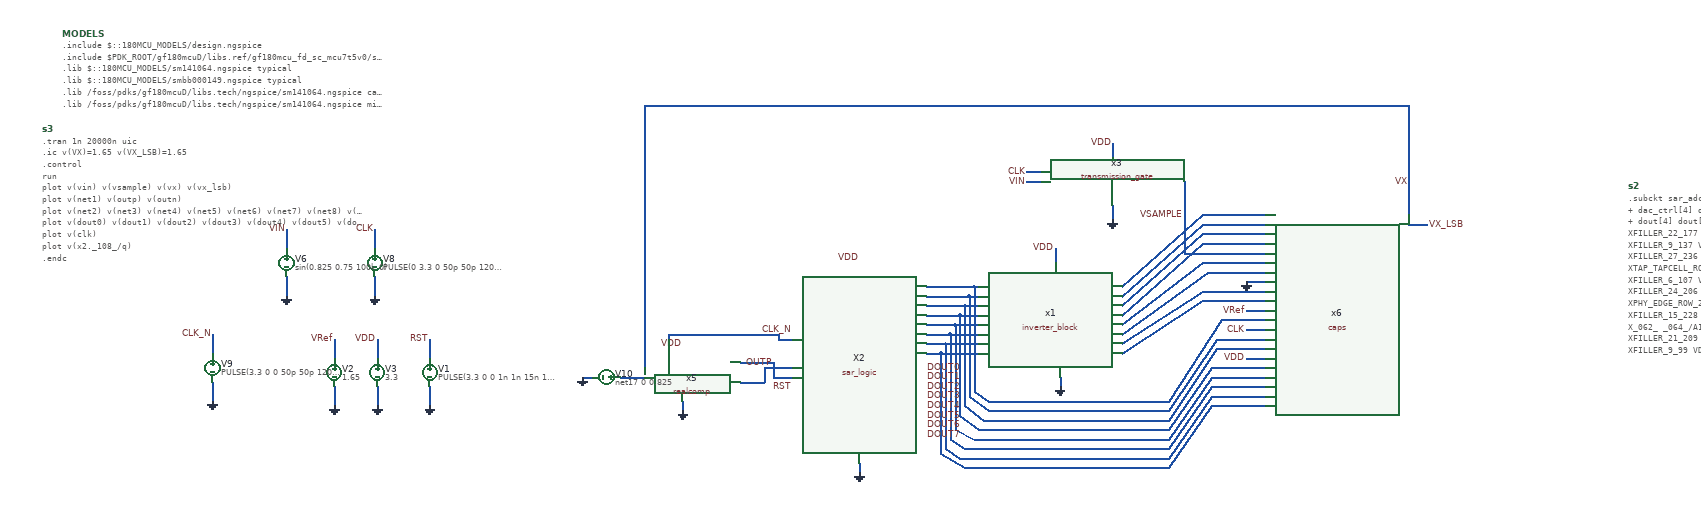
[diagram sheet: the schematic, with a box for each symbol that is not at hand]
v {xschem version=3.4.8RC file_version=1.3}
G {}
K {}
V {}
S {}
F {}
E {}
N 880 -1180 880 -1150 {lab=VDD}
N 1160 -890 1200 -890 {lab=0}
N 1160 -730 1200 -730 {lab=VDD}
N 700 -1120 730 -1120 {lab=CLK}
N 700 -1100 730 -1100 {lab=VIN}
N 1160 -830 1200 -830 {lab=VRef}
N 1160 -790 1200 -790 {lab=CLK}
N -20 -640 -20 -620 {lab=0}
N 100 -720 170 -720 {lab=OUTP}
N 880 -1050 880 -1020 {lab=0}
N 350 -510 350 -490 {lab=0}
N -50 -780 -50 -770 {lab=#net1}
N -50 -780 180 -780 {lab=#net1}
N 1030 -1100 1030 -950 {lab=VSAMPLE}
N 1030 -950 1200 -950 {lab=VSAMPLE}
N 590 -880 600 -880 {lab=#net2}
N 580 -860 600 -860 {lab=#net3}
N 570 -840 600 -840 {lab=#net4}
N 560 -820 600 -820 {lab=#net5}
N 550 -800 600 -800 {lab=#net6}
N 540 -780 600 -780 {lab=#net7}
N 530 -760 600 -760 {lab=#net8}
N 900 -880 1070 -1030 {lab=#net9}
N 1070 -1030 1200 -1030 {lab=#net9}
N 900 -860 1070 -1010 {lab=#net10}
N 1070 -1010 1200 -1010 {lab=#net10}
N 900 -840 1070 -990 {lab=#net11}
N 1070 -990 1200 -990 {lab=#net11}
N 900 -820 1070 -970 {lab=#net12}
N 1070 -970 1200 -970 {lab=#net12}
N 900 -800 1070 -930 {lab=#net13}
N 1070 -930 1200 -930 {lab=#net13}
N 900 -760 1070 -870 {lab=#net14}
N 1070 -870 1200 -870 {lab=#net14}
N 900 -740 1070 -850 {lab=#net15}
N 1070 -850 1200 -850 {lab=#net15}
N 620 -640 1000 -640 {lab=#net2}
N 620 -620 1000 -620 {lab=#net3}
N 1500 -1260 1500 -1030 {lab=VX}
N 1500 -1010 1540 -1010 {lab=VX_LSB}
N -665 -900 -665 -860 {lab=0}
N -665 -1000 -665 -960 {lab=CLK}
N -660 -670 -660 -630 {lab=0}
N -660 -770 -660 -730 {lab=VDD}
N -550 -670 -550 -630 {lab=0}
N -550 -770 -550 -730 {lab=RST}
N 760 -960 760 -930 {lab=VDD}
N 770 -690 770 -670 {lab=0}
N 590 -880 590 -660 {lab=#net2}
N 590 -660 620 -640 {lab=#net2}
N 580 -860 580 -650 {lab=#net3}
N 580 -650 620 -620 {lab=#net3}
N 570 -840 570 -630 {lab=#net4}
N 570 -630 610 -600 {lab=#net4}
N 610 -600 1000 -600 {lab=#net4}
N 560 -820 560 -610 {lab=#net5}
N 560 -610 600 -580 {lab=#net5}
N 600 -580 1000 -580 {lab=#net5}
N 550 -800 550 -580 {lab=#net6}
N 550 -580 590 -560 {lab=#net6}
N 590 -560 1000 -560 {lab=#net6}
N 540 -780 540 -560 {lab=#net7}
N 540 -560 570 -540 {lab=#net7}
N 570 -540 1000 -540 {lab=#net7}
N 490 -880 590 -880 {lab=#net2}
N 490 -860 580 -860 {lab=#net3}
N 490 -840 570 -840 {lab=#net4}
N 490 -820 560 -820 {lab=#net5}
N 490 -800 550 -800 {lab=#net6}
N 490 -780 540 -780 {lab=#net7}
N 490 -760 530 -760 {lab=#net8}
N 530 -760 530 -540 {lab=#net8}
N 530 -540 560 -520 {lab=#net8}
N 560 -520 1000 -520 {lab=#net8}
N 520 -740 600 -740 {lab=#net16}
N 520 -740 520 -530 {lab=#net16}
N 520 -530 570 -500 {lab=#net16}
N 570 -500 1000 -500 {lab=#net16}
N -100 -1260 -100 -710 {lab=VX}
N -100 -1260 1500 -1260 {lab=VX}
N -150 -690 -100 -690 {lab=#net17}
N -850 -1000 -850 -960 {lab=VIN}
N -850 -900 -850 -860 {lab=0}
N -750 -670 -750 -630 {lab=0}
N -750 -770 -750 -730 {lab=VRef}
N 1000 -640 1110 -810 {lab=#net2}
N 1110 -810 1200 -810 {lab=#net2}
N 1000 -620 1100 -770 {lab=#net3}
N 1100 -770 1200 -770 {lab=#net3}
N 1000 -600 1100 -750 {lab=#net4}
N 1100 -750 1200 -750 {lab=#net4}
N 1000 -580 1090 -710 {lab=#net5}
N 1090 -710 1200 -710 {lab=#net5}
N 1000 -560 1090 -690 {lab=#net6}
N 1090 -690 1200 -690 {lab=#net6}
N 1000 -540 1090 -670 {lab=#net7}
N 1090 -670 1200 -670 {lab=#net7}
N 1000 -520 1090 -650 {lab=#net8}
N 1090 -650 1200 -650 {lab=#net8}
N 1000 -500 1090 -630 {lab=#net16}
N 1090 -630 1200 -630 {lab=#net16}
N 900 -780 1080 -910 {lab=#net18}
N 1080 -910 1200 -910 {lab=#net18}
N 180 -780 180 -770 {lab=#net1}
N 180 -770 210 -770 {lab=#net1}
N 100 -680 150 -680 {lab=#net19}
N 150 -710 150 -680 {lab=#net19}
N 150 -710 210 -710 {lab=#net19}
N 170 -720 170 -690 {lab=OUTP}
N 170 -690 210 -690 {lab=OUTP}
N -1005 -680 -1005 -640 {lab=0}
N -1005 -780 -1005 -740 {lab=CLK_N}
N -230 -690 -210 -690 {lab=0}
N 490 -740 520 -740 {lab=#net16}
C {lab_wire.sym} 880 -1180 0 0 {name=p1 sig_type=std_logic lab=VDD}
C {lab_wire.sym} 1160 -730 0 0 {name=p2 sig_type=std_logic lab=VDD}
C {lab_wire.sym} 1160 -790 0 0 {name=p8 sig_type=std_logic lab=CLK}
C {lab_wire.sym} -20 -760 1 0 {name=p9 sig_type=std_logic lab=VDD}
C {code_shown.sym} 1960 -1090 0 0 {name=s2 only_toplevel=false 
value="
.subckt sar_adc_logic VDD VSS clk_i clk_o dac_ctrl[0] dac_ctrl[1] dac_ctrl[2] dac_ctrl[3]
+ dac_ctrl[4] dac_ctrl[5] dac_ctrl[6] dac_ctrl[7] dout[0] dout[1] dout[2] dout[3]
+ dout[4] dout[5] dout[6] dout[7] out_n out_p rst_n
XFILLER_22_177 VDD VDD VSS VSS gf180mcu_fd_sc_mcu7t5v0__fillcap_16
XFILLER_9_137 VDD VDD VSS VSS gf180mcu_fd_sc_mcu7t5v0__fill_2
XFILLER_27_236 VDD VDD VSS VSS gf180mcu_fd_sc_mcu7t5v0__fillcap_4
XTAP_TAPCELL_ROW_8_88 VDD VSS gf180mcu_fd_sc_mcu7t5v0__filltie
XFILLER_6_107 VDD VDD VSS VSS gf180mcu_fd_sc_mcu7t5v0__fill_1
XFILLER_24_206 VDD VDD VSS VSS gf180mcu_fd_sc_mcu7t5v0__fill_1
XPHY_EDGE_ROW_20_Left_50 VDD VDD VSS VSS gf180mcu_fd_sc_mcu7t5v0__endcap
XFILLER_15_228 VDD VDD VSS VSS gf180mcu_fd_sc_mcu7t5v0__fillcap_8
X_062_ _064_/A1 _105_/Q _106_/Q _063_/B VDD VDD VSS VSS gf180mcu_fd_sc_mcu7t5v0__aoi21_1
XFILLER_21_209 VDD VDD VSS VSS gf180mcu_fd_sc_mcu7t5v0__fill_1
XFILLER_9_99 VDD VDD VSS VSS gf180mcu_fd_sc_mcu7t5v0__fill_2
XFILLER_9_88 VDD VDD VSS VSS gf180mcu_fd_sc_mcu7t5v0__fill_1
XFILLER_9_66 VDD VDD VSS VSS gf180mcu_fd_sc_mcu7t5v0__fillcap_4
XFILLER_18_53 VDD VDD VSS VSS gf180mcu_fd_sc_mcu7t5v0__fillcap_8
X_045_ _087_/Q _057_/A1 VDD VDD VSS VSS gf180mcu_fd_sc_mcu7t5v0__clkinv_1
XFILLER_28_183 VDD VDD VSS VSS gf180mcu_fd_sc_mcu7t5v0__fillcap_32
Xhold30 _083_/Q _097_/D VDD VDD VSS VSS gf180mcu_fd_sc_mcu7t5v0__dlyc_1
XFILLER_4_227 VDD VDD VSS VSS gf180mcu_fd_sc_mcu7t5v0__fillcap_8
Xrebuffer28 _108_/Q wire22/I VDD VDD VSS VSS gf180mcu_fd_sc_mcu7t5v0__buf_8
XFILLER_6_34 VDD VDD VSS VSS gf180mcu_fd_sc_mcu7t5v0__fill_1
XFILLER_15_98 VDD VDD VSS VSS gf180mcu_fd_sc_mcu7t5v0__fill_1
XFILLER_25_120 VDD VDD VSS VSS gf180mcu_fd_sc_mcu7t5v0__fill_1
XFILLER_16_197 VDD VDD VSS VSS gf180mcu_fd_sc_mcu7t5v0__fill_2
Xoutput7 _086_/Q dac_ctrl[3] VDD VDD VSS VSS gf180mcu_fd_sc_mcu7t5v0__dlyd_1
XFILLER_22_101 VDD VDD VSS VSS gf180mcu_fd_sc_mcu7t5v0__fillcap_4
XFILLER_22_123 VDD VDD VSS VSS gf180mcu_fd_sc_mcu7t5v0__fill_2
XFILLER_10_159 VDD VDD VSS VSS gf180mcu_fd_sc_mcu7t5v0__fillcap_4
XTAP_TAPCELL_ROW_8_89 VDD VSS gf180mcu_fd_sc_mcu7t5v0__filltie
XFILLER_23_240 VDD VDD VSS VSS gf180mcu_fd_sc_mcu7t5v0__fill_1
XPHY_EDGE_ROW_21_Right_21 VDD VDD VSS VSS gf180mcu_fd_sc_mcu7t5v0__endcap
XPHY_EDGE_ROW_12_Right_12 VDD VDD VSS VSS gf180mcu_fd_sc_mcu7t5v0__endcap
XFILLER_0_36 VDD VDD VSS VSS gf180mcu_fd_sc_mcu7t5v0__fillcap_32
XFILLER_14_240 VDD VDD VSS VSS gf180mcu_fd_sc_mcu7t5v0__fill_1
XFILLER_2_177 VDD VDD VSS VSS gf180mcu_fd_sc_mcu7t5v0__fillcap_16
X_061_ _061_/A1 _104_/Q _061_/B _085_/D VDD VDD VSS VSS gf180mcu_fd_sc_mcu7t5v0__oai21_1
XFILLER_3_2 VDD VDD VSS VSS gf180mcu_fd_sc_mcu7t5v0__fillcap_64
XFILLER_18_65 VDD VDD VSS VSS gf180mcu_fd_sc_mcu7t5v0__fill_1
X_044_ _088_/Q _055_/A1 VDD VDD VSS VSS gf180mcu_fd_sc_mcu7t5v0__clkinv_1
XTAP_TAPCELL_ROW_5_79 VDD VSS gf180mcu_fd_sc_mcu7t5v0__filltie
Xclkbuf_1_1__f_valid_clk_regs clkbuf_0_valid_clk_regs/Z _104_/CLK VDD VDD VSS VSS
+ gf180mcu_fd_sc_mcu7t5v0__clkbuf_16
Xhold31 _089_/Q _091_/D VDD VDD VSS VSS gf180mcu_fd_sc_mcu7t5v0__dlyc_1
XFILLER_4_239 VDD VDD VSS VSS gf180mcu_fd_sc_mcu7t5v0__fill_2
XFILLER_28_173 VDD VDD VSS VSS gf180mcu_fd_sc_mcu7t5v0__fill_2
XFILLER_15_66 VDD VDD VSS VSS gf180mcu_fd_sc_mcu7t5v0__fillcap_4
XPHY_EDGE_ROW_6_Right_6 VDD VDD VSS VSS gf180mcu_fd_sc_mcu7t5v0__endcap
Xoutput10 _083_/Q dac_ctrl[6] VDD VDD VSS VSS gf180mcu_fd_sc_mcu7t5v0__dlyd_1
Xoutput8 _085_/Q dac_ctrl[4] VDD VDD VSS VSS gf180mcu_fd_sc_mcu7t5v0__dlyd_1
XFILLER_9_139 VDD VDD VSS VSS gf180mcu_fd_sc_mcu7t5v0__fill_1
Xdly_stage\\[31\\].delay_buf dly_stage\\[31\\].delay_buf/I comp_trigger_driver/I VDD VDD
+ VSS VSS gf180mcu_fd_sc_mcu7t5v0__buf_1
XFILLER_12_34 VDD VDD VSS VSS gf180mcu_fd_sc_mcu7t5v0__fill_1
XFILLER_18_227 VDD VDD VSS VSS gf180mcu_fd_sc_mcu7t5v0__fillcap_8
XFILLER_23_66 VDD VDD VSS VSS gf180mcu_fd_sc_mcu7t5v0__fillcap_4
XFILLER_2_123 VDD VDD VSS VSS gf180mcu_fd_sc_mcu7t5v0__fillcap_4
X_060_ _064_/A1 _104_/Q _105_/Q _061_/B VDD VDD VSS VSS gf180mcu_fd_sc_mcu7t5v0__aoi21_1
XFILLER_29_2 VDD VDD VSS VSS gf180mcu_fd_sc_mcu7t5v0__fillcap_32
X_043_ _089_/Q _053_/A1 VDD VDD VSS VSS gf180mcu_fd_sc_mcu7t5v0__clkinv_1
XPHY_EDGE_ROW_8_Left_38 VDD VDD VSS VSS gf180mcu_fd_sc_mcu7t5v0__endcap
XFILLER_7_237 VDD VDD VSS VSS gf180mcu_fd_sc_mcu7t5v0__fillcap_4
XFILLER_20_34 VDD VDD VSS VSS gf180mcu_fd_sc_mcu7t5v0__fill_1
Xhold32 _084_/Q _096_/D VDD VDD VSS VSS gf180mcu_fd_sc_mcu7t5v0__dlyc_1
XFILLER_6_69 VDD VDD VSS VSS gf180mcu_fd_sc_mcu7t5v0__fill_2
XFILLER_15_89 VDD VDD VSS VSS gf180mcu_fd_sc_mcu7t5v0__fill_1
XFILLER_16_111 VDD VDD VSS VSS gf180mcu_fd_sc_mcu7t5v0__fill_2
Xdly_stage\\[30\\].delay_buf dly_stage\\[30\\].delay_buf/I dly_stage\\[31\\].delay_buf/I
+ VDD VDD VSS VSS gf180mcu_fd_sc_mcu7t5v0__buf_1
Xoutput11 _090_/Q dac_ctrl[7] VDD VDD VSS VSS gf180mcu_fd_sc_mcu7t5v0__dlyd_1
Xoutput9 _084_/Q dac_ctrl[5] VDD VDD VSS VSS gf180mcu_fd_sc_mcu7t5v0__dlyd_1
XFILLER_16_177 VDD VDD VSS VSS gf180mcu_fd_sc_mcu7t5v0__fillcap_16
XFILLER_16_199 VDD VDD VSS VSS gf180mcu_fd_sc_mcu7t5v0__fill_1
XFILLER_13_136 VDD VDD VSS VSS gf180mcu_fd_sc_mcu7t5v0__fillcap_4
XTAP_TAPCELL_ROW_15_109 VDD VSS gf180mcu_fd_sc_mcu7t5v0__filltie
XFILLER_12_57 VDD VDD VSS VSS gf180mcu_fd_sc_mcu7t5v0__fill_2
XFILLER_27_228 VDD VDD VSS VSS gf180mcu_fd_sc_mcu7t5v0__fillcap_8
XFILLER_18_239 VDD VDD VSS VSS gf180mcu_fd_sc_mcu7t5v0__fill_2
XPHY_EDGE_ROW_24_Left_54 VDD VDD VSS VSS gf180mcu_fd_sc_mcu7t5v0__endcap
X_042_ _107_/Q _108_/D VDD VDD VSS VSS gf180mcu_fd_sc_mcu7t5v0__clkinv_1
Xhold33 _085_/Q _095_/D VDD VDD VSS VSS gf180mcu_fd_sc_mcu7t5v0__dlyc_1
XFILLER_6_37 VDD VDD VSS VSS gf180mcu_fd_sc_mcu7t5v0__fillcap_32
XFILLER_19_142 VDD VDD VSS VSS gf180mcu_fd_sc_mcu7t5v0__fill_1
XFILLER_25_167 VDD VDD VSS VSS gf180mcu_fd_sc_mcu7t5v0__fill_1
XFILLER_25_178 VDD VDD VSS VSS gf180mcu_fd_sc_mcu7t5v0__fill_1
Xoutput12 _091_/Q dout[0] VDD VDD VSS VSS gf180mcu_fd_sc_mcu7t5v0__dlyd_1
XPHY_EDGE_ROW_11_Left_41 VDD VDD VSS VSS gf180mcu_fd_sc_mcu7t5v0__endcap
XFILLER_16_101 VDD VDD VSS VSS gf180mcu_fd_sc_mcu7t5v0__fillcap_4
XTAP_TAPCELL_ROW_18_118 VDD VSS gf180mcu_fd_sc_mcu7t5v0__filltie
XFILLER_26_34 VDD VDD VSS VSS gf180mcu_fd_sc_mcu7t5v0__fill_1
XFILLER_7_80 VDD VDD VSS VSS gf180mcu_fd_sc_mcu7t5v0__fillcap_4
XFILLER_10_107 VDD VDD VSS VSS gf180mcu_fd_sc_mcu7t5v0__fill_2
XTAP_TAPCELL_ROW_20_124 VDD VSS gf180mcu_fd_sc_mcu7t5v0__filltie
XFILLER_5_133 VDD VDD VSS VSS gf180mcu_fd_sc_mcu7t5v0__fill_2
XFILLER_5_122 VDD VDD VSS VSS gf180mcu_fd_sc_mcu7t5v0__fill_2
XTAP_TAPCELL_ROW_0_60 VDD VSS gf180mcu_fd_sc_mcu7t5v0__filltie
XFILLER_18_24 VDD VDD VSS VSS gf180mcu_fd_sc_mcu7t5v0__fill_2
XTAP_TAPCELL_ROW_9_91 VDD VSS gf180mcu_fd_sc_mcu7t5v0__filltie
XFILLER_1_2 VDD VDD VSS VSS gf180mcu_fd_sc_mcu7t5v0__fillcap_32
Xclkload0 _107_/CLK clkload0/ZN VDD VDD VSS VSS gf180mcu_fd_sc_mcu7t5v0__inv_2
Xhold34 _088_/Q _092_/D VDD VDD VSS VSS gf180mcu_fd_sc_mcu7t5v0__dlyc_1
Xcomp_trigger_driver comp_trigger_driver/I output3/I VDD VDD VSS VSS gf180mcu_fd_sc_mcu7t5v0__buf_16
Xoutput13 _092_/Q dout[1] VDD VDD VSS VSS gf180mcu_fd_sc_mcu7t5v0__dlyd_1
XFILLER_24_190 VDD VDD VSS VSS gf180mcu_fd_sc_mcu7t5v0__fillcap_16
XTAP_TAPCELL_ROW_18_119 VDD VSS gf180mcu_fd_sc_mcu7t5v0__filltie
XPHY_EDGE_ROW_28_Right_28 VDD VDD VSS VSS gf180mcu_fd_sc_mcu7t5v0__endcap
XPHY_EDGE_ROW_19_Right_19 VDD VDD VSS VSS gf180mcu_fd_sc_mcu7t5v0__endcap
XTAP_TAPCELL_ROW_23_133 VDD VSS gf180mcu_fd_sc_mcu7t5v0__filltie
XFILLER_12_37 VDD VDD VSS VSS gf180mcu_fd_sc_mcu7t5v0__fillcap_16
XTAP_TAPCELL_ROW_20_125 VDD VSS gf180mcu_fd_sc_mcu7t5v0__filltie
Xclkbuf_0_valid_clk valid_clk_xor/Z clkbuf_0_valid_clk/Z VDD VDD VSS VSS gf180mcu_fd_sc_mcu7t5v0__clkbuf_16
XTAP_TAPCELL_ROW_9_92 VDD VSS gf180mcu_fd_sc_mcu7t5v0__filltie
XTAP_TAPCELL_ROW_0_61 VDD VSS gf180mcu_fd_sc_mcu7t5v0__filltie
XFILLER_27_2 VDD VDD VSS VSS gf180mcu_fd_sc_mcu7t5v0__fillcap_64
XFILLER_20_37 VDD VDD VSS VSS gf180mcu_fd_sc_mcu7t5v0__fillcap_64
Xhold35 _087_/Q _093_/D VDD VDD VSS VSS gf180mcu_fd_sc_mcu7t5v0__dlyc_1
XTAP_TAPCELL_ROW_6_82 VDD VSS gf180mcu_fd_sc_mcu7t5v0__filltie
Xclkbuf_1_0__f_eoc clkbuf_0_eoc/Z comp_trigger_nor/A2 VDD VDD VSS VSS gf180mcu_fd_sc_mcu7t5v0__clkbuf_16
Xoutput14 _093_/Q dout[2] VDD VDD VSS VSS gf180mcu_fd_sc_mcu7t5v0__dlyd_1
XTAP_TAPCELL_ROW_26_142 VDD VSS gf180mcu_fd_sc_mcu7t5v0__filltie
XFILLER_7_93 VDD VDD VSS VSS gf180mcu_fd_sc_mcu7t5v0__fill_1
XTAP_TAPCELL_ROW_23_134 VDD VSS gf180mcu_fd_sc_mcu7t5v0__filltie
XFILLER_27_209 VDD VDD VSS VSS gf180mcu_fd_sc_mcu7t5v0__fill_1
XTAP_TAPCELL_ROW_20_126 VDD VSS gf180mcu_fd_sc_mcu7t5v0__filltie
XFILLER_5_135 VDD VDD VSS VSS gf180mcu_fd_sc_mcu7t5v0__fill_1
XFILLER_5_124 VDD VDD VSS VSS gf180mcu_fd_sc_mcu7t5v0__fill_1
XFILLER_23_212 VDD VDD VSS VSS gf180mcu_fd_sc_mcu7t5v0__fillcap_16
XFILLER_4_61 VDD VDD VSS VSS gf180mcu_fd_sc_mcu7t5v0__fill_1
XFILLER_2_127 VDD VDD VSS VSS gf180mcu_fd_sc_mcu7t5v0__fill_2
XTAP_TAPCELL_ROW_9_93 VDD VSS gf180mcu_fd_sc_mcu7t5v0__filltie
XTAP_TAPCELL_ROW_0_62 VDD VSS gf180mcu_fd_sc_mcu7t5v0__filltie
XFILLER_18_26 VDD VDD VSS VSS gf180mcu_fd_sc_mcu7t5v0__fill_1
XFILLER_18_37 VDD VDD VSS VSS gf180mcu_fd_sc_mcu7t5v0__fillcap_16
X_099_ _100_/Q _099_/RN _104_/CLK _099_/Q VDD VDD VSS VSS gf180mcu_fd_sc_mcu7t5v0__dffrnq_1
XPHY_EDGE_ROW_28_Left_58 VDD VDD VSS VSS gf180mcu_fd_sc_mcu7t5v0__endcap
XFILLER_28_101 VDD VDD VSS VSS gf180mcu_fd_sc_mcu7t5v0__fillcap_4
XFILLER_29_36 VDD VDD VSS VSS gf180mcu_fd_sc_mcu7t5v0__fillcap_32
Xhold36 _086_/Q _094_/D VDD VDD VSS VSS gf180mcu_fd_sc_mcu7t5v0__dlyc_1
XTAP_TAPCELL_ROW_29_151 VDD VSS gf180mcu_fd_sc_mcu7t5v0__filltie
XFILLER_25_104 VDD VDD VSS VSS gf180mcu_fd_sc_mcu7t5v0__fillcap_16
XTAP_TAPCELL_ROW_6_83 VDD VSS gf180mcu_fd_sc_mcu7t5v0__filltie
XFILLER_0_203 VDD VDD VSS VSS gf180mcu_fd_sc_mcu7t5v0__fill_1
XFILLER_24_181 VDD VDD VSS VSS gf180mcu_fd_sc_mcu7t5v0__fill_2
Xoutput15 _094_/Q dout[3] VDD VDD VSS VSS gf180mcu_fd_sc_mcu7t5v0__dlyd_1
XTAP_TAPCELL_ROW_26_143 VDD VSS gf180mcu_fd_sc_mcu7t5v0__filltie
XPHY_EDGE_ROW_1_Right_1 VDD VDD VSS VSS gf180mcu_fd_sc_mcu7t5v0__endcap
XFILLER_22_107 VDD VDD VSS VSS gf180mcu_fd_sc_mcu7t5v0__fillcap_16
XPHY_EDGE_ROW_15_Left_45 VDD VDD VSS VSS gf180mcu_fd_sc_mcu7t5v0__endcap
XFILLER_7_72 VDD VDD VSS VSS gf180mcu_fd_sc_mcu7t5v0__fillcap_8
XFILLER_26_37 VDD VDD VSS VSS gf180mcu_fd_sc_mcu7t5v0__fillcap_64
XTAP_TAPCELL_ROW_23_135 VDD VSS gf180mcu_fd_sc_mcu7t5v0__filltie
XFILLER_29_240 VDD VDD VSS VSS gf180mcu_fd_sc_mcu7t5v0__fill_1
XTAP_TAPCELL_ROW_3_73 VDD VSS gf180mcu_fd_sc_mcu7t5v0__filltie
XTAP_TAPCELL_ROW_0_63 VDD VSS gf180mcu_fd_sc_mcu7t5v0__filltie
XFILLER_11_238 VDD VDD VSS VSS gf180mcu_fd_sc_mcu7t5v0__fill_2
X_098_ _098_/D _050_/I _098_/CLK _098_/Q VDD VDD VSS VSS gf180mcu_fd_sc_mcu7t5v0__dffrnq_1
XPHY_EDGE_ROW_3_Left_33 VDD VDD VSS VSS gf180mcu_fd_sc_mcu7t5v0__endcap
XFILLER_10_61 VDD VDD VSS VSS gf180mcu_fd_sc_mcu7t5v0__fillcap_4
X_107__27 _107_/D VDD VDD VSS VSS gf180mcu_fd_sc_mcu7t5v0__tiel
Xhold37 _090_/Q _098_/D VDD VDD VSS VSS gf180mcu_fd_sc_mcu7t5v0__dlyc_1
XTAP_TAPCELL_ROW_10_94 VDD VSS gf180mcu_fd_sc_mcu7t5v0__filltie
XTAP_TAPCELL_ROW_6_84 VDD VSS gf180mcu_fd_sc_mcu7t5v0__filltie
XTAP_TAPCELL_ROW_29_152 VDD VSS gf180mcu_fd_sc_mcu7t5v0__filltie
XFILLER_16_149 VDD VDD VSS VSS gf180mcu_fd_sc_mcu7t5v0__fill_1
Xoutput16 _095_/Q dout[4] VDD VDD VSS VSS gf180mcu_fd_sc_mcu7t5v0__dlyd_1
XTAP_TAPCELL_ROW_26_144 VDD VSS gf180mcu_fd_sc_mcu7t5v0__filltie
XFILLER_21_152 VDD VDD VSS VSS gf180mcu_fd_sc_mcu7t5v0__fill_1
XPHY_EDGE_ROW_24_Right_24 VDD VDD VSS VSS gf180mcu_fd_sc_mcu7t5v0__endcap
XPHY_EDGE_ROW_15_Right_15 VDD VDD VSS VSS gf180mcu_fd_sc_mcu7t5v0__endcap
XFILLER_7_84 VDD VDD VSS VSS gf180mcu_fd_sc_mcu7t5v0__fill_2
XFILLER_12_185 VDD VDD VSS VSS gf180mcu_fd_sc_mcu7t5v0__fillcap_4
XTAP_TAPCELL_ROW_3_74 VDD VSS gf180mcu_fd_sc_mcu7t5v0__filltie
XFILLER_8_101 VDD VDD VSS VSS gf180mcu_fd_sc_mcu7t5v0__fillcap_4
XFILLER_23_236 VDD VDD VSS VSS gf180mcu_fd_sc_mcu7t5v0__fillcap_4
XFILLER_2_107 VDD VDD VSS VSS gf180mcu_fd_sc_mcu7t5v0__fillcap_16
XFILLER_2_129 VDD VDD VSS VSS gf180mcu_fd_sc_mcu7t5v0__fill_1
XFILLER_13_72 VDD VDD VSS VSS gf180mcu_fd_sc_mcu7t5v0__fillcap_64
XFILLER_14_236 VDD VDD VSS VSS gf180mcu_fd_sc_mcu7t5v0__fillcap_4
XTAP_TAPCELL_ROW_0_64 VDD VSS gf180mcu_fd_sc_mcu7t5v0__filltie
XFILLER_9_240 VDD VDD VSS VSS gf180mcu_fd_sc_mcu7t5v0__fill_1
X_097_ _097_/D _050_/I _098_/CLK _097_/Q VDD VDD VSS VSS gf180mcu_fd_sc_mcu7t5v0__dffrnq_1
XTAP_TAPCELL_ROW_10_95 VDD VSS gf180mcu_fd_sc_mcu7t5v0__filltie
XFILLER_3_202 VDD VDD VSS VSS gf180mcu_fd_sc_mcu7t5v0__fillcap_8
XTAP_TAPCELL_ROW_29_153 VDD VSS gf180mcu_fd_sc_mcu7t5v0__filltie
XFILLER_25_139 VDD VDD VSS VSS gf180mcu_fd_sc_mcu7t5v0__fill_1
XFILLER_25_2 VDD VDD VSS VSS gf180mcu_fd_sc_mcu7t5v0__fillcap_64
Xoutput17 _096_/Q dout[5] VDD VDD VSS VSS gf180mcu_fd_sc_mcu7t5v0__dlyd_1
XFILLER_21_72 VDD VDD VSS VSS gf180mcu_fd_sc_mcu7t5v0__fillcap_32
XFILLER_24_183 VDD VDD VSS VSS gf180mcu_fd_sc_mcu7t5v0__fill_1
XFILLER_16_61 VDD VDD VSS VSS gf180mcu_fd_sc_mcu7t5v0__fillcap_4
XFILLER_21_120 VDD VDD VSS VSS gf180mcu_fd_sc_mcu7t5v0__fillcap_8
XTAP_TAPCELL_ROW_3_75 VDD VSS gf180mcu_fd_sc_mcu7t5v0__filltie
XFILLER_4_53 VDD VDD VSS VSS gf180mcu_fd_sc_mcu7t5v0__fillcap_8
XTAP_TAPCELL_ROW_0_65 VDD VSS gf180mcu_fd_sc_mcu7t5v0__filltie
X_096_ _096_/D _050_/I _098_/CLK _096_/Q VDD VDD VSS VSS gf180mcu_fd_sc_mcu7t5v0__dffrnq_1
XTAP_TAPCELL_ROW_10_96 VDD VSS gf180mcu_fd_sc_mcu7t5v0__filltie
XFILLER_19_72 VDD VDD VSS VSS gf180mcu_fd_sc_mcu7t5v0__fillcap_4
XTAP_TAPCELL_ROW_29_154 VDD VSS gf180mcu_fd_sc_mcu7t5v0__filltie
XFILLER_0_206 VDD VDD VSS VSS gf180mcu_fd_sc_mcu7t5v0__fillcap_32
Xoutput18 _097_/Q dout[6] VDD VDD VSS VSS gf180mcu_fd_sc_mcu7t5v0__dlyd_1
X_079_ wire22/I _080_/A2 _104_/RN VDD VDD VSS VSS gf180mcu_fd_sc_mcu7t5v0__nor2_1
XFILLER_16_107 VDD VDD VSS VSS gf180mcu_fd_sc_mcu7t5v0__fillcap_4
XFILLER_15_162 VDD VDD VSS VSS gf180mcu_fd_sc_mcu7t5v0__fill_1
XFILLER_7_86 VDD VDD VSS VSS gf180mcu_fd_sc_mcu7t5v0__fill_1
XFILLER_21_132 VDD VDD VSS VSS gf180mcu_fd_sc_mcu7t5v0__fill_2
XPHY_EDGE_ROW_5_Right_5 VDD VDD VSS VSS gf180mcu_fd_sc_mcu7t5v0__endcap
XPHY_EDGE_ROW_19_Left_49 VDD VDD VSS VSS gf180mcu_fd_sc_mcu7t5v0__endcap
XFILLER_26_235 VDD VDD VSS VSS gf180mcu_fd_sc_mcu7t5v0__fillcap_4
XFILLER_27_72 VDD VDD VSS VSS gf180mcu_fd_sc_mcu7t5v0__fillcap_32
XTAP_TAPCELL_ROW_0_66 VDD VSS gf180mcu_fd_sc_mcu7t5v0__filltie
XFILLER_11_208 VDD VDD VSS VSS gf180mcu_fd_sc_mcu7t5v0__fill_2
X_095_ _095_/D _050_/I _098_/CLK _095_/Q VDD VDD VSS VSS gf180mcu_fd_sc_mcu7t5v0__dffrnq_1
XFILLER_10_53 VDD VDD VSS VSS gf180mcu_fd_sc_mcu7t5v0__fillcap_8
XFILLER_19_127 VDD VDD VSS VSS gf180mcu_fd_sc_mcu7t5v0__fill_1
XFILLER_27_193 VDD VDD VSS VSS gf180mcu_fd_sc_mcu7t5v0__fillcap_16
XTAP_TAPCELL_ROW_29_155 VDD VSS gf180mcu_fd_sc_mcu7t5v0__filltie
XPHY_EDGE_ROW_7_Left_37 VDD VDD VSS VSS gf180mcu_fd_sc_mcu7t5v0__endcap
XFILLER_3_237 VDD VDD VSS VSS gf180mcu_fd_sc_mcu7t5v0__fillcap_4
X_078_ wire22/Z _080_/A2 _103_/RN VDD VDD VSS VSS gf180mcu_fd_sc_mcu7t5v0__nor2_1
XFILLER_24_174 VDD VDD VSS VSS gf180mcu_fd_sc_mcu7t5v0__fill_1
Xoutput19 _098_/Q dout[7] VDD VDD VSS VSS gf180mcu_fd_sc_mcu7t5v0__dlyd_1
XFILLER_12_177 VDD VDD VSS VSS gf180mcu_fd_sc_mcu7t5v0__fillcap_8
XTAP_TAPCELL_ROW_14_106 VDD VSS gf180mcu_fd_sc_mcu7t5v0__filltie
XPHY_EDGE_ROW_20_Right_20 VDD VDD VSS VSS gf180mcu_fd_sc_mcu7t5v0__endcap
XPHY_EDGE_ROW_11_Right_11 VDD VDD VSS VSS gf180mcu_fd_sc_mcu7t5v0__endcap
XFILLER_23_228 VDD VDD VSS VSS gf180mcu_fd_sc_mcu7t5v0__fillcap_8
XFILLER_4_173 VDD VDD VSS VSS gf180mcu_fd_sc_mcu7t5v0__fill_2
XFILLER_8_2 VDD VDD VSS VSS gf180mcu_fd_sc_mcu7t5v0__fillcap_32
X_094_ _094_/D _050_/I _094_/CLK _094_/Q VDD VDD VSS VSS gf180mcu_fd_sc_mcu7t5v0__dffrnq_1
XFILLER_1_34 VDD VDD VSS VSS gf180mcu_fd_sc_mcu7t5v0__fill_2
XPHY_EDGE_ROW_23_Left_53 VDD VDD VSS VSS gf180mcu_fd_sc_mcu7t5v0__endcap
XTAP_TAPCELL_ROW_29_156 VDD VSS gf180mcu_fd_sc_mcu7t5v0__filltie
X_077_ wire22/Z _077_/A2 _102_/RN VDD VDD VSS VSS gf180mcu_fd_sc_mcu7t5v0__nor2_1
XFILLER_24_142 VDD VDD VSS VSS gf180mcu_fd_sc_mcu7t5v0__fillcap_32
XFILLER_15_142 VDD VDD VSS VSS gf180mcu_fd_sc_mcu7t5v0__fillcap_16
XFILLER_15_175 VDD VDD VSS VSS gf180mcu_fd_sc_mcu7t5v0__fill_1
XTAP_TAPCELL_ROW_17_115 VDD VSS gf180mcu_fd_sc_mcu7t5v0__filltie
XFILLER_7_66 VDD VDD VSS VSS gf180mcu_fd_sc_mcu7t5v0__fillcap_4
XFILLER_23_2 VDD VDD VSS VSS gf180mcu_fd_sc_mcu7t5v0__fillcap_64
XPHY_EDGE_ROW_10_Left_40 VDD VDD VSS VSS gf180mcu_fd_sc_mcu7t5v0__endcap
XFILLER_16_53 VDD VDD VSS VSS gf180mcu_fd_sc_mcu7t5v0__fillcap_8
XTAP_TAPCELL_ROW_14_107 VDD VSS gf180mcu_fd_sc_mcu7t5v0__filltie
XFILLER_17_204 VDD VDD VSS VSS gf180mcu_fd_sc_mcu7t5v0__fillcap_4
XFILLER_17_237 VDD VDD VSS VSS gf180mcu_fd_sc_mcu7t5v0__fillcap_4
XFILLER_4_34 VDD VDD VSS VSS gf180mcu_fd_sc_mcu7t5v0__fill_1
XFILLER_4_130 VDD VDD VSS VSS gf180mcu_fd_sc_mcu7t5v0__fill_1
XFILLER_13_240 VDD VDD VSS VSS gf180mcu_fd_sc_mcu7t5v0__fill_1
X_093_ _093_/D _050_/I _094_/CLK _093_/Q VDD VDD VSS VSS gf180mcu_fd_sc_mcu7t5v0__dffrnq_1
XFILLER_6_203 VDD VDD VSS VSS gf180mcu_fd_sc_mcu7t5v0__fillcap_4
XFILLER_28_107 VDD VDD VSS VSS gf180mcu_fd_sc_mcu7t5v0__fillcap_32
Xinput1 out_n input1/Z VDD VDD VSS VSS gf180mcu_fd_sc_mcu7t5v0__dlyd_1
Xclkbuf_0_valid_clk_regs clkbuf_regs_0_valid_clk/Z clkbuf_0_valid_clk_regs/Z VDD VDD
+ VSS VSS gf180mcu_fd_sc_mcu7t5v0__clkbuf_16
X_076_ wire22/Z _077_/A2 _101_/RN VDD VDD VSS VSS gf180mcu_fd_sc_mcu7t5v0__nor2_1
XTAP_TAPCELL_ROW_29_157 VDD VSS gf180mcu_fd_sc_mcu7t5v0__filltie
XFILLER_18_173 VDD VDD VSS VSS gf180mcu_fd_sc_mcu7t5v0__fill_2
XTAP_TAPCELL_ROW_17_116 VDD VSS gf180mcu_fd_sc_mcu7t5v0__filltie
XFILLER_16_2 VDD VDD VSS VSS gf180mcu_fd_sc_mcu7t5v0__fillcap_32
X_059_ _059_/A1 _103_/Q _059_/B _086_/D VDD VDD VSS VSS gf180mcu_fd_sc_mcu7t5v0__oai21_1
XTAP_TAPCELL_ROW_22_130 VDD VSS gf180mcu_fd_sc_mcu7t5v0__filltie
XTAP_TAPCELL_ROW_14_108 VDD VSS gf180mcu_fd_sc_mcu7t5v0__filltie
XPHY_EDGE_ROW_9_Right_9 VDD VDD VSS VSS gf180mcu_fd_sc_mcu7t5v0__endcap
XFILLER_26_227 VDD VDD VSS VSS gf180mcu_fd_sc_mcu7t5v0__fillcap_8
XFILLER_23_208 VDD VDD VSS VSS gf180mcu_fd_sc_mcu7t5v0__fill_2
XFILLER_13_66 VDD VDD VSS VSS gf180mcu_fd_sc_mcu7t5v0__fillcap_4
XFILLER_9_212 VDD VDD VSS VSS gf180mcu_fd_sc_mcu7t5v0__fillcap_16
Xclkbuf_0_eoc_regs clkbuf_0_eoc_regs/I clkbuf_0_eoc_regs/Z VDD VDD VSS VSS gf180mcu_fd_sc_mcu7t5v0__clkbuf_16
X_092_ _092_/D _050_/I _094_/CLK _092_/Q VDD VDD VSS VSS gf180mcu_fd_sc_mcu7t5v0__dffrnq_1
XFILLER_10_34 VDD VDD VSS VSS gf180mcu_fd_sc_mcu7t5v0__fill_1
Xinput2 out_p wire26/I VDD VDD VSS VSS gf180mcu_fd_sc_mcu7t5v0__buf_1
XFILLER_19_119 VDD VDD VSS VSS gf180mcu_fd_sc_mcu7t5v0__fillcap_8
XFILLER_19_76 VDD VDD VSS VSS gf180mcu_fd_sc_mcu7t5v0__fill_2
XFILLER_19_87 VDD VDD VSS VSS gf180mcu_fd_sc_mcu7t5v0__fillcap_32
XFILLER_27_152 VDD VDD VSS VSS gf180mcu_fd_sc_mcu7t5v0__fill_1
X_075_ _108_/Q _077_/A2 _100_/RN VDD VDD VSS VSS gf180mcu_fd_sc_mcu7t5v0__nor2_1
XFILLER_21_66 VDD VDD VSS VSS gf180mcu_fd_sc_mcu7t5v0__fillcap_4
XFILLER_24_177 VDD VDD VSS VSS gf180mcu_fd_sc_mcu7t5v0__fillcap_4
Xmax_cap20 _080_/A2 _082_/A2 VDD VDD VSS VSS gf180mcu_fd_sc_mcu7t5v0__buf_2
XTAP_TAPCELL_ROW_17_117 VDD VSS gf180mcu_fd_sc_mcu7t5v0__filltie
X_058_ wire26/Z _103_/Q _104_/Q _059_/B VDD VDD VSS VSS gf180mcu_fd_sc_mcu7t5v0__aoi21_1
XFILLER_12_103 VDD VDD VSS VSS gf180mcu_fd_sc_mcu7t5v0__fill_2
XTAP_TAPCELL_ROW_22_131 VDD VSS gf180mcu_fd_sc_mcu7t5v0__filltie
XFILLER_8_107 VDD VDD VSS VSS gf180mcu_fd_sc_mcu7t5v0__fill_1
XFILLER_26_239 VDD VDD VSS VSS gf180mcu_fd_sc_mcu7t5v0__fill_2
XFILLER_4_165 VDD VDD VSS VSS gf180mcu_fd_sc_mcu7t5v0__fillcap_8
X_091_ _091_/D _050_/I _094_/CLK _091_/Q VDD VDD VSS VSS gf180mcu_fd_sc_mcu7t5v0__dffrnq_1
XFILLER_6_2 VDD VDD VSS VSS gf180mcu_fd_sc_mcu7t5v0__fillcap_32
XPHY_EDGE_ROW_27_Right_27 VDD VDD VSS VSS gf180mcu_fd_sc_mcu7t5v0__endcap
XPHY_EDGE_ROW_18_Right_18 VDD VDD VSS VSS gf180mcu_fd_sc_mcu7t5v0__endcap
XFILLER_27_120 VDD VDD VSS VSS gf180mcu_fd_sc_mcu7t5v0__fillcap_8
X_074_ _108_/Q _077_/A2 _099_/RN VDD VDD VSS VSS gf180mcu_fd_sc_mcu7t5v0__nor2_1
XPHY_EDGE_ROW_27_Left_57 VDD VDD VSS VSS gf180mcu_fd_sc_mcu7t5v0__endcap
XFILLER_24_101 VDD VDD VSS VSS gf180mcu_fd_sc_mcu7t5v0__fillcap_4
XFILLER_24_123 VDD VDD VSS VSS gf180mcu_fd_sc_mcu7t5v0__fillcap_4
Xclkbuf_1_0__f_valid_clk clkbuf_0_valid_clk/Z comp_trigger_nor/A1 VDD VDD VSS VSS
+ gf180mcu_fd_sc_mcu7t5v0__clkbuf_16
Xmax_cap21 _080_/A2 _077_/A2 VDD VDD VSS VSS gf180mcu_fd_sc_mcu7t5v0__buf_2
X_057_ _057_/A1 _102_/Q _057_/B _087_/D VDD VDD VSS VSS gf180mcu_fd_sc_mcu7t5v0__oai21_1
XTAP_TAPCELL_ROW_25_140 VDD VSS gf180mcu_fd_sc_mcu7t5v0__filltie
XFILLER_16_34 VDD VDD VSS VSS gf180mcu_fd_sc_mcu7t5v0__fill_1
XFILLER_21_104 VDD VDD VSS VSS gf180mcu_fd_sc_mcu7t5v0__fillcap_16
XFILLER_21_148 VDD VDD VSS VSS gf180mcu_fd_sc_mcu7t5v0__fillcap_4
XFILLER_12_159 VDD VDD VSS VSS gf180mcu_fd_sc_mcu7t5v0__fillcap_16
XTAP_TAPCELL_ROW_22_132 VDD VSS gf180mcu_fd_sc_mcu7t5v0__filltie
XPHY_EDGE_ROW_0_Right_0 VDD VDD VSS VSS gf180mcu_fd_sc_mcu7t5v0__endcap
XFILLER_21_2 VDD VDD VSS VSS gf180mcu_fd_sc_mcu7t5v0__fillcap_64
XPHY_EDGE_ROW_14_Left_44 VDD VDD VSS VSS gf180mcu_fd_sc_mcu7t5v0__endcap
XFILLER_25_240 VDD VDD VSS VSS gf180mcu_fd_sc_mcu7t5v0__fill_1
XFILLER_27_66 VDD VDD VSS VSS gf180mcu_fd_sc_mcu7t5v0__fillcap_4
XFILLER_16_240 VDD VDD VSS VSS gf180mcu_fd_sc_mcu7t5v0__fill_1
XFILLER_4_37 VDD VDD VSS VSS gf180mcu_fd_sc_mcu7t5v0__fillcap_16
XFILLER_4_100 VDD VDD VSS VSS gf180mcu_fd_sc_mcu7t5v0__fillcap_4
XFILLER_9_236 VDD VDD VSS VSS gf180mcu_fd_sc_mcu7t5v0__fillcap_4
XFILLER_5_80 VDD VDD VSS VSS gf180mcu_fd_sc_mcu7t5v0__fillcap_4
XFILLER_10_235 VDD VDD VSS VSS gf180mcu_fd_sc_mcu7t5v0__fillcap_4
XFILLER_24_34 VDD VDD VSS VSS gf180mcu_fd_sc_mcu7t5v0__fill_1
X_090_ _090_/D _073_/ZN _107_/CLK _090_/Q VDD VDD VSS VSS gf180mcu_fd_sc_mcu7t5v0__dffsnq_1
XFILLER_19_78 VDD VDD VSS VSS gf180mcu_fd_sc_mcu7t5v0__fill_1
XFILLER_18_8 VDD VDD VSS VSS gf180mcu_fd_sc_mcu7t5v0__fillcap_16
X_073_ wire22/Z _082_/A2 _073_/ZN VDD VDD VSS VSS gf180mcu_fd_sc_mcu7t5v0__nor2_1
XPHY_EDGE_ROW_2_Left_32 VDD VDD VSS VSS gf180mcu_fd_sc_mcu7t5v0__endcap
X_056_ wire26/Z _102_/Q _103_/Q _057_/B VDD VDD VSS VSS gf180mcu_fd_sc_mcu7t5v0__aoi21_2
XTAP_TAPCELL_ROW_25_141 VDD VSS gf180mcu_fd_sc_mcu7t5v0__filltie
XFILLER_14_2 VDD VDD VSS VSS gf180mcu_fd_sc_mcu7t5v0__fillcap_32
X_108_ _108_/D _050_/I clk_i _108_/Q VDD VDD VSS VSS gf180mcu_fd_sc_mcu7t5v0__dffrnq_4
XFILLER_17_208 VDD VDD VSS VSS gf180mcu_fd_sc_mcu7t5v0__fill_2
XFILLER_14_90 VDD VDD VSS VSS gf180mcu_fd_sc_mcu7t5v0__fillcap_8
XFILLER_5_240 VDD VDD VSS VSS gf180mcu_fd_sc_mcu7t5v0__fill_1
XFILLER_10_37 VDD VDD VSS VSS gf180mcu_fd_sc_mcu7t5v0__fillcap_16
XFILLER_19_68 VDD VDD VSS VSS gf180mcu_fd_sc_mcu7t5v0__fill_2
X_072_ _108_/Q _077_/A2 _089_/RN VDD VDD VSS VSS gf180mcu_fd_sc_mcu7t5v0__nor2_1
XTAP_TAPCELL_ROW_28_150 VDD VSS gf180mcu_fd_sc_mcu7t5v0__filltie
XFILLER_15_158 VDD VDD VSS VSS gf180mcu_fd_sc_mcu7t5v0__fillcap_4
Xdly_stage\\[19\\].delay_buf dly_stage\\[19\\].delay_buf/I dly_stage\\[20\\].delay_buf/I
+ VDD VDD VSS VSS gf180mcu_fd_sc_mcu7t5v0__buf_1
X_055_ _055_/A1 _101_/Q _055_/B _088_/D VDD VDD VSS VSS gf180mcu_fd_sc_mcu7t5v0__oai21_1
XFILLER_11_80 VDD VDD VSS VSS gf180mcu_fd_sc_mcu7t5v0__fillcap_4
XFILLER_21_128 VDD VDD VSS VSS gf180mcu_fd_sc_mcu7t5v0__fillcap_4
XFILLER_29_206 VDD VDD VSS VSS gf180mcu_fd_sc_mcu7t5v0__fillcap_32
X_107_ _107_/D _082_/ZN _107_/CLK _107_/Q VDD VDD VSS VSS gf180mcu_fd_sc_mcu7t5v0__dffsnq_2
XFILLER_4_124 VDD VDD VSS VSS gf180mcu_fd_sc_mcu7t5v0__fill_1
XFILLER_22_201 VDD VDD VSS VSS gf180mcu_fd_sc_mcu7t5v0__fillcap_4
XFILLER_13_212 VDD VDD VSS VSS gf180mcu_fd_sc_mcu7t5v0__fillcap_16
XFILLER_19_36 VDD VDD VSS VSS gf180mcu_fd_sc_mcu7t5v0__fillcap_32
XFILLER_2_233 VDD VDD VSS VSS gf180mcu_fd_sc_mcu7t5v0__fillcap_8
Xdly_stage\\[18\\].delay_buf dly_stage\\[18\\].delay_buf/I dly_stage\\[19\\].delay_buf/I
+ VDD VDD VSS VSS gf180mcu_fd_sc_mcu7t5v0__buf_1
X_071_ _108_/Q _077_/A2 _088_/RN VDD VDD VSS VSS gf180mcu_fd_sc_mcu7t5v0__nor2_1
XPHY_EDGE_ROW_23_Right_23 VDD VDD VSS VSS gf180mcu_fd_sc_mcu7t5v0__endcap
XPHY_EDGE_ROW_14_Right_14 VDD VDD VSS VSS gf180mcu_fd_sc_mcu7t5v0__endcap
XFILLER_4_2 VDD VDD VSS VSS gf180mcu_fd_sc_mcu7t5v0__fillcap_32
XFILLER_15_137 VDD VDD VSS VSS gf180mcu_fd_sc_mcu7t5v0__fill_2
XFILLER_23_192 VDD VDD VSS VSS gf180mcu_fd_sc_mcu7t5v0__fillcap_16
X_054_ _064_/A1 _101_/Q _102_/Q _055_/B VDD VDD VSS VSS gf180mcu_fd_sc_mcu7t5v0__aoi21_1
XFILLER_12_107 VDD VDD VSS VSS gf180mcu_fd_sc_mcu7t5v0__fill_2
XFILLER_16_37 VDD VDD VSS VSS gf180mcu_fd_sc_mcu7t5v0__fillcap_16
XFILLER_20_173 VDD VDD VSS VSS gf180mcu_fd_sc_mcu7t5v0__fill_2
X_106_ _107_/Q _106_/RN _107_/CLK _106_/Q VDD VDD VSS VSS gf180mcu_fd_sc_mcu7t5v0__dffrnq_2
XFILLER_19_240 VDD VDD VSS VSS gf180mcu_fd_sc_mcu7t5v0__fill_1
XPHY_EDGE_ROW_4_Right_4 VDD VDD VSS VSS gf180mcu_fd_sc_mcu7t5v0__endcap
XPHY_EDGE_ROW_18_Left_48 VDD VDD VSS VSS gf180mcu_fd_sc_mcu7t5v0__endcap
XFILLER_0_172 VDD VDD VSS VSS gf180mcu_fd_sc_mcu7t5v0__fillcap_4
XFILLER_9_228 VDD VDD VSS VSS gf180mcu_fd_sc_mcu7t5v0__fillcap_8
XFILLER_10_227 VDD VDD VSS VSS gf180mcu_fd_sc_mcu7t5v0__fillcap_8
XFILLER_24_37 VDD VDD VSS VSS gf180mcu_fd_sc_mcu7t5v0__fillcap_64
Xdly_stage\\[17\\].delay_buf dly_stage\\[17\\].delay_buf/I dly_stage\\[18\\].delay_buf/I
+ VDD VDD VSS VSS gf180mcu_fd_sc_mcu7t5v0__buf_1
XFILLER_5_72 VDD VDD VSS VSS gf180mcu_fd_sc_mcu7t5v0__fillcap_8
XFILLER_14_81 VDD VDD VSS VSS gf180mcu_fd_sc_mcu7t5v0__fill_2
X_070_ wire22/Z _077_/A2 _087_/RN VDD VDD VSS VSS gf180mcu_fd_sc_mcu7t5v0__nor2_1
XFILLER_18_102 VDD VDD VSS VSS gf180mcu_fd_sc_mcu7t5v0__fill_2
XFILLER_15_105 VDD VDD VSS VSS gf180mcu_fd_sc_mcu7t5v0__fillcap_32
XFILLER_24_127 VDD VDD VSS VSS gf180mcu_fd_sc_mcu7t5v0__fill_2
Xmax_cap25 wire26/Z _064_/A1 VDD VDD VSS VSS gf180mcu_fd_sc_mcu7t5v0__buf_2
XPHY_EDGE_ROW_6_Left_36 VDD VDD VSS VSS gf180mcu_fd_sc_mcu7t5v0__endcap
XFILLER_11_93 VDD VDD VSS VSS gf180mcu_fd_sc_mcu7t5v0__fillcap_16
X_053_ _053_/A1 _100_/Q _053_/B _089_/D VDD VDD VSS VSS gf180mcu_fd_sc_mcu7t5v0__oai21_1
XFILLER_20_185 VDD VDD VSS VSS gf180mcu_fd_sc_mcu7t5v0__fillcap_4
X_105_ _106_/Q _105_/RN _107_/CLK _105_/Q VDD VDD VSS VSS gf180mcu_fd_sc_mcu7t5v0__dffrnq_2
XTAP_TAPCELL_ROW_13_103 VDD VSS gf180mcu_fd_sc_mcu7t5v0__filltie
XFILLER_4_104 VDD VDD VSS VSS gf180mcu_fd_sc_mcu7t5v0__fill_1
XFILLER_12_2 VDD VDD VSS VSS gf180mcu_fd_sc_mcu7t5v0__fillcap_32
Xdly_stage\\[16\\].delay_buf dly_stage\\[16\\].delay_buf/I dly_stage\\[17\\].delay_buf/I
+ VDD VDD VSS VSS gf180mcu_fd_sc_mcu7t5v0__buf_1
XFILLER_13_236 VDD VDD VSS VSS gf180mcu_fd_sc_mcu7t5v0__fillcap_4
XFILLER_5_84 VDD VDD VSS VSS gf180mcu_fd_sc_mcu7t5v0__fill_2
XFILLER_10_239 VDD VDD VSS VSS gf180mcu_fd_sc_mcu7t5v0__fill_2
XFILLER_18_169 VDD VDD VSS VSS gf180mcu_fd_sc_mcu7t5v0__fillcap_4
XPHY_EDGE_ROW_22_Left_52 VDD VDD VSS VSS gf180mcu_fd_sc_mcu7t5v0__endcap
XFILLER_15_139 VDD VDD VSS VSS gf180mcu_fd_sc_mcu7t5v0__fill_1
X_052_ _064_/A1 _100_/Q _101_/Q _053_/B VDD VDD VSS VSS gf180mcu_fd_sc_mcu7t5v0__aoi21_1
XFILLER_14_161 VDD VDD VSS VSS gf180mcu_fd_sc_mcu7t5v0__fill_2
XTAP_TAPCELL_ROW_16_112 VDD VSS gf180mcu_fd_sc_mcu7t5v0__filltie
XFILLER_20_131 VDD VDD VSS VSS gf180mcu_fd_sc_mcu7t5v0__fillcap_4
XFILLER_28_231 VDD VDD VSS VSS gf180mcu_fd_sc_mcu7t5v0__fillcap_8
XTAP_TAPCELL_ROW_13_104 VDD VSS gf180mcu_fd_sc_mcu7t5v0__filltie
XFILLER_11_131 VDD VDD VSS VSS gf180mcu_fd_sc_mcu7t5v0__fill_1
XFILLER_11_164 VDD VDD VSS VSS gf180mcu_fd_sc_mcu7t5v0__fill_2
X_104_ _105_/Q _104_/RN _104_/CLK _104_/Q VDD VDD VSS VSS gf180mcu_fd_sc_mcu7t5v0__dffrnq_2
Xdly_stage\\[15\\].delay_buf dly_stage\\[15\\].delay_buf/I dly_stage\\[16\\].delay_buf/I
+ VDD VDD VSS VSS gf180mcu_fd_sc_mcu7t5v0__buf_1
XFILLER_25_201 VDD VDD VSS VSS gf180mcu_fd_sc_mcu7t5v0__fillcap_8
XFILLER_25_212 VDD VDD VSS VSS gf180mcu_fd_sc_mcu7t5v0__fillcap_16
XFILLER_16_234 VDD VDD VSS VSS gf180mcu_fd_sc_mcu7t5v0__fillcap_4
Xclkbuf_regs_1_eoc_clk _099_/Q clkbuf_0_eoc_regs/I VDD VDD VSS VSS gf180mcu_fd_sc_mcu7t5v0__clkbuf_16
Xclkbuf_1_1__f_eoc_regs clkbuf_0_eoc_regs/Z _094_/CLK VDD VDD VSS VSS gf180mcu_fd_sc_mcu7t5v0__clkbuf_16
XFILLER_14_83 VDD VDD VSS VSS gf180mcu_fd_sc_mcu7t5v0__fill_1
XFILLER_27_104 VDD VDD VSS VSS gf180mcu_fd_sc_mcu7t5v0__fillcap_16
XFILLER_27_148 VDD VDD VSS VSS gf180mcu_fd_sc_mcu7t5v0__fillcap_4
XFILLER_18_104 VDD VDD VSS VSS gf180mcu_fd_sc_mcu7t5v0__fill_1
XFILLER_18_115 VDD VDD VSS VSS gf180mcu_fd_sc_mcu7t5v0__fillcap_4
XFILLER_24_107 VDD VDD VSS VSS gf180mcu_fd_sc_mcu7t5v0__fillcap_16
XFILLER_24_129 VDD VDD VSS VSS gf180mcu_fd_sc_mcu7t5v0__fill_1
XTAP_TAPCELL_ROW_19_121 VDD VSS gf180mcu_fd_sc_mcu7t5v0__filltie
XPHY_EDGE_ROW_10_Right_10 VDD VDD VSS VSS gf180mcu_fd_sc_mcu7t5v0__endcap
XFILLER_11_84 VDD VDD VSS VSS gf180mcu_fd_sc_mcu7t5v0__fill_2
XFILLER_2_2 VDD VDD VSS VSS gf180mcu_fd_sc_mcu7t5v0__fillcap_32
X_051_ _090_/Q wire26/Z _107_/Q _090_/D VDD VDD VSS VSS gf180mcu_fd_sc_mcu7t5v0__mux2_2
Xdly_stage\\[14\\].delay_buf dly_stage\\[14\\].delay_buf/I dly_stage\\[15\\].delay_buf/I
+ VDD VDD VSS VSS gf180mcu_fd_sc_mcu7t5v0__buf_1
XTAP_TAPCELL_ROW_7_85 VDD VSS gf180mcu_fd_sc_mcu7t5v0__filltie
XTAP_TAPCELL_ROW_16_113 VDD VSS gf180mcu_fd_sc_mcu7t5v0__filltie
XFILLER_20_165 VDD VDD VSS VSS gf180mcu_fd_sc_mcu7t5v0__fillcap_8
X_103_ _104_/Q _103_/RN _104_/CLK _103_/Q VDD VDD VSS VSS gf180mcu_fd_sc_mcu7t5v0__dffrnq_2
XTAP_TAPCELL_ROW_13_105 VDD VSS gf180mcu_fd_sc_mcu7t5v0__filltie
Xdly_stage\\[9\\].delay_buf dly_stage\\[9\\].delay_buf/I dly_stage\\[9\\].delay_buf/Z VDD
+ VDD VSS VSS gf180mcu_fd_sc_mcu7t5v0__buf_1
XFILLER_17_50 VDD VDD VSS VSS gf180mcu_fd_sc_mcu7t5v0__fillcap_8
XFILLER_22_205 VDD VDD VSS VSS gf180mcu_fd_sc_mcu7t5v0__fill_2
Xclkbuf_1_0__f_eoc_regs clkbuf_0_eoc_regs/Z _098_/CLK VDD VDD VSS VSS gf180mcu_fd_sc_mcu7t5v0__clkbuf_16
XPHY_EDGE_ROW_8_Right_8 VDD VDD VSS VSS gf180mcu_fd_sc_mcu7t5v0__endcap
XFILLER_3_150 VDD VDD VSS VSS gf180mcu_fd_sc_mcu7t5v0__fill_2
Xvalid_clk_xor wire26/Z input1/Z valid_clk_xor/Z VDD VDD VSS VSS gf180mcu_fd_sc_mcu7t5v0__xor2_4
XFILLER_9_209 VDD VDD VSS VSS gf180mcu_fd_sc_mcu7t5v0__fill_1
XFILLER_5_212 VDD VDD VSS VSS gf180mcu_fd_sc_mcu7t5v0__fillcap_16
XFILLER_25_72 VDD VDD VSS VSS gf180mcu_fd_sc_mcu7t5v0__fillcap_32
Xdly_stage\\[13\\].delay_buf dly_stage\\[13\\].delay_buf/I dly_stage\\[14\\].delay_buf/I
+ VDD VDD VSS VSS gf180mcu_fd_sc_mcu7t5v0__buf_1
XTAP_TAPCELL_ROW_19_122 VDD VSS gf180mcu_fd_sc_mcu7t5v0__filltie
X_050_ _050_/I _080_/A2 VDD VDD VSS VSS gf180mcu_fd_sc_mcu7t5v0__inv_1
XFILLER_11_52 VDD VDD VSS VSS gf180mcu_fd_sc_mcu7t5v0__fillcap_4
Xdly_stage\\[8\\].delay_buf dly_stage\\[8\\].delay_buf/I dly_stage\\[9\\].delay_buf/I VDD
+ VDD VSS VSS gf180mcu_fd_sc_mcu7t5v0__buf_1
XTAP_TAPCELL_ROW_7_86 VDD VSS gf180mcu_fd_sc_mcu7t5v0__filltie
XTAP_TAPCELL_ROW_16_114 VDD VSS gf180mcu_fd_sc_mcu7t5v0__filltie
XFILLER_20_177 VDD VDD VSS VSS gf180mcu_fd_sc_mcu7t5v0__fillcap_8
XFILLER_28_2 VDD VDD VSS VSS gf180mcu_fd_sc_mcu7t5v0__fillcap_32
X_102_ _103_/Q _102_/RN _104_/CLK _102_/Q VDD VDD VSS VSS gf180mcu_fd_sc_mcu7t5v0__dffrnq_2
XFILLER_25_236 VDD VDD VSS VSS gf180mcu_fd_sc_mcu7t5v0__fillcap_4
XFILLER_4_107 VDD VDD VSS VSS gf180mcu_fd_sc_mcu7t5v0__fill_2
XTAP_TAPCELL_ROW_4_76 VDD VSS gf180mcu_fd_sc_mcu7t5v0__filltie
XFILLER_13_228 VDD VDD VSS VSS gf180mcu_fd_sc_mcu7t5v0__fillcap_8
Xcomp_trigger_nor comp_trigger_nor/A1 comp_trigger_nor/A2 _108_/Q comp_trigger_nor/ZN
+ VDD VDD VSS VSS gf180mcu_fd_sc_mcu7t5v0__nor3_4
XFILLER_0_176 VDD VDD VSS VSS gf180mcu_fd_sc_mcu7t5v0__fill_2
XFILLER_10_2 VDD VDD VSS VSS gf180mcu_fd_sc_mcu7t5v0__fillcap_32
Xdly_stage\\[12\\].delay_buf dly_stage\\[12\\].delay_buf/I dly_stage\\[13\\].delay_buf/I
+ VDD VDD VSS VSS gf180mcu_fd_sc_mcu7t5v0__buf_1
Xdly_stage\\[7\\].delay_buf dly_stage\\[7\\].delay_buf/I dly_stage\\[8\\].delay_buf/I VDD
+ VDD VSS VSS gf180mcu_fd_sc_mcu7t5v0__buf_1
XTAP_TAPCELL_ROW_19_123 VDD VSS gf180mcu_fd_sc_mcu7t5v0__filltie
XFILLER_23_120 VDD VDD VSS VSS gf180mcu_fd_sc_mcu7t5v0__fillcap_8
XTAP_TAPCELL_ROW_11_97 VDD VSS gf180mcu_fd_sc_mcu7t5v0__filltie
XFILLER_11_86 VDD VDD VSS VSS gf180mcu_fd_sc_mcu7t5v0__fill_1
XTAP_TAPCELL_ROW_7_87 VDD VSS gf180mcu_fd_sc_mcu7t5v0__filltie
XPHY_EDGE_ROW_26_Left_56 VDD VDD VSS VSS gf180mcu_fd_sc_mcu7t5v0__endcap
XFILLER_20_101 VDD VDD VSS VSS gf180mcu_fd_sc_mcu7t5v0__fillcap_4
XFILLER_20_123 VDD VDD VSS VSS gf180mcu_fd_sc_mcu7t5v0__fillcap_8
XFILLER_20_189 VDD VDD VSS VSS gf180mcu_fd_sc_mcu7t5v0__fill_2
XFILLER_11_156 VDD VDD VSS VSS gf180mcu_fd_sc_mcu7t5v0__fillcap_8
X_101_ _102_/Q _101_/RN _104_/CLK _101_/Q VDD VDD VSS VSS gf180mcu_fd_sc_mcu7t5v0__dffrnq_2
XFILLER_19_212 VDD VDD VSS VSS gf180mcu_fd_sc_mcu7t5v0__fillcap_16
XTAP_TAPCELL_ROW_4_77 VDD VSS gf180mcu_fd_sc_mcu7t5v0__filltie
Xdly_stage\\[11\\].delay_buf dly_stage\\[11\\].delay_buf/I dly_stage\\[12\\].delay_buf/I
+ VDD VDD VSS VSS gf180mcu_fd_sc_mcu7t5v0__buf_1
XPHY_EDGE_ROW_13_Left_43 VDD VDD VSS VSS gf180mcu_fd_sc_mcu7t5v0__endcap
XFILLER_21_240 VDD VDD VSS VSS gf180mcu_fd_sc_mcu7t5v0__fill_1
XFILLER_5_66 VDD VDD VSS VSS gf180mcu_fd_sc_mcu7t5v0__fillcap_4
Xdly_stage\\[6\\].delay_buf dly_stage\\[6\\].delay_buf/I dly_stage\\[7\\].delay_buf/I VDD
+ VDD VSS VSS gf180mcu_fd_sc_mcu7t5v0__buf_1
XFILLER_5_236 VDD VDD VSS VSS gf180mcu_fd_sc_mcu7t5v0__fillcap_4
XTAP_TAPCELL_ROW_1_67 VDD VSS gf180mcu_fd_sc_mcu7t5v0__filltie
XFILLER_18_107 VDD VDD VSS VSS gf180mcu_fd_sc_mcu7t5v0__fillcap_8
XFILLER_26_195 VDD VDD VSS VSS gf180mcu_fd_sc_mcu7t5v0__fillcap_32
XFILLER_2_34 VDD VDD VSS VSS gf180mcu_fd_sc_mcu7t5v0__fill_1
Xclkbuf_1_0__f_valid_clk_regs clkbuf_0_valid_clk_regs/Z _107_/CLK VDD VDD VSS VSS
+ gf180mcu_fd_sc_mcu7t5v0__clkbuf_16
XTAP_TAPCELL_ROW_11_98 VDD VSS gf180mcu_fd_sc_mcu7t5v0__filltie
XFILLER_23_132 VDD VDD VSS VSS gf180mcu_fd_sc_mcu7t5v0__fill_2
XPHY_EDGE_ROW_1_Left_31 VDD VDD VSS VSS gf180mcu_fd_sc_mcu7t5v0__endcap
XFILLER_11_146 VDD VDD VSS VSS gf180mcu_fd_sc_mcu7t5v0__fill_2
X_100_ _101_/Q _100_/RN _104_/CLK _100_/Q VDD VDD VSS VSS gf180mcu_fd_sc_mcu7t5v0__dffrnq_2
XFILLER_0_2 VDD VDD VSS VSS gf180mcu_fd_sc_mcu7t5v0__fillcap_32
XFILLER_6_172 VDD VDD VSS VSS gf180mcu_fd_sc_mcu7t5v0__fill_2
Xdly_stage\\[10\\].delay_buf dly_stage\\[9\\].delay_buf/Z dly_stage\\[11\\].delay_buf/I
+ VDD VDD VSS VSS gf180mcu_fd_sc_mcu7t5v0__buf_1
XFILLER_4_109 VDD VDD VSS VSS gf180mcu_fd_sc_mcu7t5v0__fill_1
XFILLER_16_238 VDD VDD VSS VSS gf180mcu_fd_sc_mcu7t5v0__fill_2
Xdly_stage\\[29\\].delay_buf dly_stage\\[29\\].delay_buf/I dly_stage\\[30\\].delay_buf/I
+ VDD VDD VSS VSS gf180mcu_fd_sc_mcu7t5v0__buf_1
XTAP_TAPCELL_ROW_4_78 VDD VSS gf180mcu_fd_sc_mcu7t5v0__filltie
XFILLER_3_186 VDD VDD VSS VSS gf180mcu_fd_sc_mcu7t5v0__fillcap_16
XFILLER_3_142 VDD VDD VSS VSS gf180mcu_fd_sc_mcu7t5v0__fillcap_8
Xdly_stage\\[5\\].delay_buf dly_stage\\[5\\].delay_buf/I dly_stage\\[6\\].delay_buf/I VDD
+ VDD VSS VSS gf180mcu_fd_sc_mcu7t5v0__buf_1
XPHY_EDGE_ROW_26_Right_26 VDD VDD VSS VSS gf180mcu_fd_sc_mcu7t5v0__endcap
XPHY_EDGE_ROW_17_Right_17 VDD VDD VSS VSS gf180mcu_fd_sc_mcu7t5v0__endcap
XFILLER_14_98 VDD VDD VSS VSS gf180mcu_fd_sc_mcu7t5v0__fillcap_4
XTAP_TAPCELL_ROW_1_68 VDD VSS gf180mcu_fd_sc_mcu7t5v0__filltie
XFILLER_1_240 VDD VDD VSS VSS gf180mcu_fd_sc_mcu7t5v0__fill_1
XFILLER_26_174 VDD VDD VSS VSS gf180mcu_fd_sc_mcu7t5v0__fill_1
XFILLER_17_130 VDD VDD VSS VSS gf180mcu_fd_sc_mcu7t5v0__fill_2
XTAP_TAPCELL_ROW_25_139 VDD VSS gf180mcu_fd_sc_mcu7t5v0__filltie
XTAP_TAPCELL_ROW_11_99 VDD VSS gf180mcu_fd_sc_mcu7t5v0__filltie
Xdly_stage\\[28\\].delay_buf dly_stage\\[28\\].delay_buf/I dly_stage\\[29\\].delay_buf/I
+ VDD VDD VSS VSS gf180mcu_fd_sc_mcu7t5v0__buf_1
XFILLER_19_236 VDD VDD VSS VSS gf180mcu_fd_sc_mcu7t5v0__fillcap_4
XFILLER_8_34 VDD VDD VSS VSS gf180mcu_fd_sc_mcu7t5v0__fill_1
XFILLER_25_228 VDD VDD VSS VSS gf180mcu_fd_sc_mcu7t5v0__fillcap_8
XFILLER_26_2 VDD VDD VSS VSS gf180mcu_fd_sc_mcu7t5v0__fillcap_32
Xdly_stage\\[4\\].delay_buf dly_stage\\[4\\].delay_buf/I dly_stage\\[5\\].delay_buf/I VDD
+ VDD VSS VSS gf180mcu_fd_sc_mcu7t5v0__buf_1
XFILLER_17_76 VDD VDD VSS VSS gf180mcu_fd_sc_mcu7t5v0__fill_2
XFILLER_8_235 VDD VDD VSS VSS gf180mcu_fd_sc_mcu7t5v0__fillcap_4
XFILLER_14_77 VDD VDD VSS VSS gf180mcu_fd_sc_mcu7t5v0__fillcap_4
XFILLER_29_172 VDD VDD VSS VSS gf180mcu_fd_sc_mcu7t5v0__fillcap_32
XTAP_TAPCELL_ROW_1_69 VDD VSS gf180mcu_fd_sc_mcu7t5v0__filltie
XTAP_TAPCELL_ROW_28_148 VDD VSS gf180mcu_fd_sc_mcu7t5v0__filltie
XFILLER_2_69 VDD VDD VSS VSS gf180mcu_fd_sc_mcu7t5v0__fill_2
XFILLER_11_56 VDD VDD VSS VSS gf180mcu_fd_sc_mcu7t5v0__fill_2
Xdly_stage\\[27\\].delay_buf dly_stage\\[27\\].delay_buf/I dly_stage\\[28\\].delay_buf/I
+ VDD VDD VSS VSS gf180mcu_fd_sc_mcu7t5v0__buf_1
XFILLER_28_215 VDD VDD VSS VSS gf180mcu_fd_sc_mcu7t5v0__fillcap_16
Xdly_stage\\[3\\].delay_buf dly_stage\\[3\\].delay_buf/I dly_stage\\[4\\].delay_buf/I VDD
+ VDD VSS VSS gf180mcu_fd_sc_mcu7t5v0__buf_1
X_089_ _089_/D _089_/RN _104_/CLK _089_/Q VDD VDD VSS VSS gf180mcu_fd_sc_mcu7t5v0__dffrnq_2
XFILLER_6_174 VDD VDD VSS VSS gf180mcu_fd_sc_mcu7t5v0__fill_1
XFILLER_15_240 VDD VDD VSS VSS gf180mcu_fd_sc_mcu7t5v0__fill_1
XPHY_EDGE_ROW_3_Right_3 VDD VDD VSS VSS gf180mcu_fd_sc_mcu7t5v0__endcap
XPHY_EDGE_ROW_17_Left_47 VDD VDD VSS VSS gf180mcu_fd_sc_mcu7t5v0__endcap
XFILLER_14_34 VDD VDD VSS VSS gf180mcu_fd_sc_mcu7t5v0__fill_1
XFILLER_29_140 VDD VDD VSS VSS gf180mcu_fd_sc_mcu7t5v0__fill_1
XFILLER_5_228 VDD VDD VSS VSS gf180mcu_fd_sc_mcu7t5v0__fillcap_8
Xdly_stage\\[26\\].delay_buf dly_stage\\[26\\].delay_buf/I dly_stage\\[27\\].delay_buf/I
+ VDD VDD VSS VSS gf180mcu_fd_sc_mcu7t5v0__buf_1
XFILLER_25_66 VDD VDD VSS VSS gf180mcu_fd_sc_mcu7t5v0__fillcap_4
XTAP_TAPCELL_ROW_28_149 VDD VSS gf180mcu_fd_sc_mcu7t5v0__filltie
XFILLER_2_37 VDD VDD VSS VSS gf180mcu_fd_sc_mcu7t5v0__fillcap_32
Xdly_stage\\[2\\].delay_buf dly_stage\\[2\\].delay_buf/I dly_stage\\[3\\].delay_buf/I VDD
+ VDD VSS VSS gf180mcu_fd_sc_mcu7t5v0__buf_1
Xrst_root rst_n _050_/I VDD VDD VSS VSS gf180mcu_fd_sc_mcu7t5v0__buf_8
XFILLER_14_102 VDD VDD VSS VSS gf180mcu_fd_sc_mcu7t5v0__fill_2
XFILLER_14_157 VDD VDD VSS VSS gf180mcu_fd_sc_mcu7t5v0__fillcap_4
XFILLER_22_34 VDD VDD VSS VSS gf180mcu_fd_sc_mcu7t5v0__fill_1
XPHY_EDGE_ROW_5_Left_35 VDD VDD VSS VSS gf180mcu_fd_sc_mcu7t5v0__endcap
X_088_ _088_/D _088_/RN _104_/CLK _088_/Q VDD VDD VSS VSS gf180mcu_fd_sc_mcu7t5v0__dffrnq_2
XTAP_TAPCELL_ROW_12_100 VDD VSS gf180mcu_fd_sc_mcu7t5v0__filltie
XFILLER_17_34 VDD VDD VSS VSS gf180mcu_fd_sc_mcu7t5v0__fillcap_16
XTAP_TAPCELL_ROW_8_90 VDD VSS gf180mcu_fd_sc_mcu7t5v0__filltie
XFILLER_0_70 VDD VDD VSS VSS gf180mcu_fd_sc_mcu7t5v0__fillcap_16
XFILLER_0_104 VDD VDD VSS VSS gf180mcu_fd_sc_mcu7t5v0__fillcap_32
Xdly_stage\\[25\\].delay_buf dly_stage\\[25\\].delay_buf/I dly_stage\\[26\\].delay_buf/I
+ VDD VDD VSS VSS gf180mcu_fd_sc_mcu7t5v0__buf_1
XTAP_TAPCELL_ROW_5_80 VDD VSS gf180mcu_fd_sc_mcu7t5v0__filltie
XPHY_EDGE_ROW_22_Right_22 VDD VDD VSS VSS gf180mcu_fd_sc_mcu7t5v0__endcap
XPHY_EDGE_ROW_13_Right_13 VDD VDD VSS VSS gf180mcu_fd_sc_mcu7t5v0__endcap
XFILLER_29_163 VDD VDD VSS VSS gf180mcu_fd_sc_mcu7t5v0__fillcap_4
Xdly_stage\\[1\\].delay_buf dly_stage\\[1\\].delay_buf/I dly_stage\\[2\\].delay_buf/I VDD
+ VDD VSS VSS gf180mcu_fd_sc_mcu7t5v0__buf_1
XFILLER_17_122 VDD VDD VSS VSS gf180mcu_fd_sc_mcu7t5v0__fillcap_8
XFILLER_17_188 VDD VDD VSS VSS gf180mcu_fd_sc_mcu7t5v0__fillcap_16
XFILLER_9_2 VDD VDD VSS VSS gf180mcu_fd_sc_mcu7t5v0__fillcap_64
XTAP_TAPCELL_ROW_2_70 VDD VSS gf180mcu_fd_sc_mcu7t5v0__filltie
XFILLER_11_36 VDD VDD VSS VSS gf180mcu_fd_sc_mcu7t5v0__fillcap_16
XPHY_EDGE_ROW_21_Left_51 VDD VDD VSS VSS gf180mcu_fd_sc_mcu7t5v0__endcap
XFILLER_28_239 VDD VDD VSS VSS gf180mcu_fd_sc_mcu7t5v0__fill_2
XFILLER_19_228 VDD VDD VSS VSS gf180mcu_fd_sc_mcu7t5v0__fillcap_8
X_087_ _087_/D _087_/RN _104_/CLK _087_/Q VDD VDD VSS VSS gf180mcu_fd_sc_mcu7t5v0__dffrnq_2
XTAP_TAPCELL_ROW_12_101 VDD VSS gf180mcu_fd_sc_mcu7t5v0__filltie
XFILLER_8_37 VDD VDD VSS VSS gf180mcu_fd_sc_mcu7t5v0__fillcap_64
XFILLER_25_209 VDD VDD VSS VSS gf180mcu_fd_sc_mcu7t5v0__fill_1
Xdly_stage\\[24\\].delay_buf dly_stage\\[24\\].delay_buf/I dly_stage\\[25\\].delay_buf/I
+ VDD VDD VSS VSS gf180mcu_fd_sc_mcu7t5v0__buf_1
XFILLER_21_212 VDD VDD VSS VSS gf180mcu_fd_sc_mcu7t5v0__fillcap_16
XFILLER_24_2 VDD VDD VSS VSS gf180mcu_fd_sc_mcu7t5v0__fillcap_32
XFILLER_0_138 VDD VDD VSS VSS gf180mcu_fd_sc_mcu7t5v0__fillcap_32
XFILLER_28_34 VDD VDD VSS VSS gf180mcu_fd_sc_mcu7t5v0__fill_1
Xdly_stage\\[0\\].delay_buf comp_trigger_nor/ZN dly_stage\\[1\\].delay_buf/I VDD VDD VSS
+ VSS gf180mcu_fd_sc_mcu7t5v0__buf_1
XFILLER_8_227 VDD VDD VSS VSS gf180mcu_fd_sc_mcu7t5v0__fillcap_8
XTAP_TAPCELL_ROW_5_81 VDD VSS gf180mcu_fd_sc_mcu7t5v0__filltie
XFILLER_14_69 VDD VDD VSS VSS gf180mcu_fd_sc_mcu7t5v0__fillcap_8
XFILLER_26_101 VDD VDD VSS VSS gf180mcu_fd_sc_mcu7t5v0__fillcap_4
XFILLER_26_123 VDD VDD VSS VSS gf180mcu_fd_sc_mcu7t5v0__fill_2
XFILLER_23_104 VDD VDD VSS VSS gf180mcu_fd_sc_mcu7t5v0__fillcap_16
XTAP_TAPCELL_ROW_2_71 VDD VSS gf180mcu_fd_sc_mcu7t5v0__filltie
XFILLER_14_104 VDD VDD VSS VSS gf180mcu_fd_sc_mcu7t5v0__fill_1
XFILLER_20_107 VDD VDD VSS VSS gf180mcu_fd_sc_mcu7t5v0__fillcap_16
XTAP_TAPCELL_ROW_15_110 VDD VSS gf180mcu_fd_sc_mcu7t5v0__filltie
Xwire22 wire22/I wire22/Z VDD VDD VSS VSS gf180mcu_fd_sc_mcu7t5v0__buf_2
XFILLER_27_240 VDD VDD VSS VSS gf180mcu_fd_sc_mcu7t5v0__fill_1
Xdly_stage\\[23\\].delay_buf dly_stage\\[23\\].delay_buf/I dly_stage\\[24\\].delay_buf/I
+ VDD VDD VSS VSS gf180mcu_fd_sc_mcu7t5v0__buf_1
X_086_ _086_/D _086_/RN _104_/CLK _086_/Q VDD VDD VSS VSS gf180mcu_fd_sc_mcu7t5v0__dffrnq_2
XTAP_TAPCELL_ROW_12_102 VDD VSS gf180mcu_fd_sc_mcu7t5v0__filltie
Xclkbuf_regs_0_valid_clk valid_clk_xor/Z clkbuf_regs_0_valid_clk/Z VDD VDD VSS VSS
+ gf180mcu_fd_sc_mcu7t5v0__clkbuf_16
XFILLER_17_58 VDD VDD VSS VSS gf180mcu_fd_sc_mcu7t5v0__fillcap_4
XFILLER_17_2 VDD VDD VSS VSS gf180mcu_fd_sc_mcu7t5v0__fillcap_32
X_069_ wire22/Z _080_/A2 _086_/RN VDD VDD VSS VSS gf180mcu_fd_sc_mcu7t5v0__nor2_1
XFILLER_8_239 VDD VDD VSS VSS gf180mcu_fd_sc_mcu7t5v0__fill_2
XFILLER_14_37 VDD VDD VSS VSS gf180mcu_fd_sc_mcu7t5v0__fillcap_32
XPHY_EDGE_ROW_7_Right_7 VDD VDD VSS VSS gf180mcu_fd_sc_mcu7t5v0__endcap
XFILLER_1_212 VDD VDD VSS VSS gf180mcu_fd_sc_mcu7t5v0__fillcap_16
Xclkbuf_0_eoc _099_/Q clkbuf_0_eoc/Z VDD VDD VSS VSS gf180mcu_fd_sc_mcu7t5v0__clkbuf_16
XTAP_TAPCELL_ROW_2_72 VDD VSS gf180mcu_fd_sc_mcu7t5v0__filltie
Xdly_stage\\[22\\].delay_buf dly_stage\\[22\\].delay_buf/I dly_stage\\[23\\].delay_buf/I
+ VDD VDD VSS VSS gf180mcu_fd_sc_mcu7t5v0__buf_1
XFILLER_22_193 VDD VDD VSS VSS gf180mcu_fd_sc_mcu7t5v0__fillcap_8
XTAP_TAPCELL_ROW_15_111 VDD VSS gf180mcu_fd_sc_mcu7t5v0__filltie
XFILLER_3_72 VDD VDD VSS VSS gf180mcu_fd_sc_mcu7t5v0__fillcap_4
XFILLER_22_37 VDD VDD VSS VSS gf180mcu_fd_sc_mcu7t5v0__fillcap_64
X_085_ _085_/D _085_/RN _107_/CLK _085_/Q VDD VDD VSS VSS gf180mcu_fd_sc_mcu7t5v0__dffrnq_2
XPHY_EDGE_ROW_9_Left_39 VDD VDD VSS VSS gf180mcu_fd_sc_mcu7t5v0__endcap
XFILLER_2_170 VDD VDD VSS VSS gf180mcu_fd_sc_mcu7t5v0__fillcap_4
X_068_ wire22/I _082_/A2 _085_/RN VDD VDD VSS VSS gf180mcu_fd_sc_mcu7t5v0__nor2_1
XFILLER_21_203 VDD VDD VSS VSS gf180mcu_fd_sc_mcu7t5v0__fillcap_4
XFILLER_21_236 VDD VDD VSS VSS gf180mcu_fd_sc_mcu7t5v0__fillcap_4
XFILLER_26_125 VDD VDD VSS VSS gf180mcu_fd_sc_mcu7t5v0__fill_1
Xdly_stage\\[21\\].delay_buf dly_stage\\[21\\].delay_buf/I dly_stage\\[22\\].delay_buf/I
+ VDD VDD VSS VSS gf180mcu_fd_sc_mcu7t5v0__buf_1
XFILLER_23_128 VDD VDD VSS VSS gf180mcu_fd_sc_mcu7t5v0__fillcap_4
XTAP_TAPCELL_ROW_18_120 VDD VSS gf180mcu_fd_sc_mcu7t5v0__filltie
XFILLER_7_2 VDD VDD VSS VSS gf180mcu_fd_sc_mcu7t5v0__fillcap_64
XFILLER_19_209 VDD VDD VSS VSS gf180mcu_fd_sc_mcu7t5v0__fill_1
XPHY_EDGE_ROW_29_Right_29 VDD VDD VSS VSS gf180mcu_fd_sc_mcu7t5v0__endcap
X_084_ _084_/D _084_/RN _107_/CLK _084_/Q VDD VDD VSS VSS gf180mcu_fd_sc_mcu7t5v0__dffrnq_1
XPHY_EDGE_ROW_25_Left_55 VDD VDD VSS VSS gf180mcu_fd_sc_mcu7t5v0__endcap
XFILLER_15_212 VDD VDD VSS VSS gf180mcu_fd_sc_mcu7t5v0__fillcap_16
XFILLER_2_193 VDD VDD VSS VSS gf180mcu_fd_sc_mcu7t5v0__fillcap_4
X_067_ _108_/Q _082_/A2 _084_/RN VDD VDD VSS VSS gf180mcu_fd_sc_mcu7t5v0__nor2_1
XFILLER_9_72 VDD VDD VSS VSS gf180mcu_fd_sc_mcu7t5v0__fillcap_16
XFILLER_28_37 VDD VDD VSS VSS gf180mcu_fd_sc_mcu7t5v0__fillcap_64
XFILLER_22_2 VDD VDD VSS VSS gf180mcu_fd_sc_mcu7t5v0__fillcap_32
Xdly_stage\\[20\\].delay_buf dly_stage\\[20\\].delay_buf/I dly_stage\\[21\\].delay_buf/I
+ VDD VDD VSS VSS gf180mcu_fd_sc_mcu7t5v0__buf_1
XFILLER_29_167 VDD VDD VSS VSS gf180mcu_fd_sc_mcu7t5v0__fill_2
XPHY_EDGE_ROW_12_Left_42 VDD VDD VSS VSS gf180mcu_fd_sc_mcu7t5v0__endcap
XFILLER_17_148 VDD VDD VSS VSS gf180mcu_fd_sc_mcu7t5v0__fillcap_4
XFILLER_1_236 VDD VDD VSS VSS gf180mcu_fd_sc_mcu7t5v0__fillcap_4
XTAP_TAPCELL_ROW_21_127 VDD VSS gf180mcu_fd_sc_mcu7t5v0__filltie
X_083_ _083_/D _083_/RN _107_/CLK _083_/Q VDD VDD VSS VSS gf180mcu_fd_sc_mcu7t5v0__dffrnq_1
XPHY_EDGE_ROW_0_Left_30 VDD VDD VSS VSS gf180mcu_fd_sc_mcu7t5v0__endcap
XFILLER_3_139 VDD VDD VSS VSS gf180mcu_fd_sc_mcu7t5v0__fill_1
XFILLER_3_117 VDD VDD VSS VSS gf180mcu_fd_sc_mcu7t5v0__fillcap_8
XFILLER_0_86 VDD VDD VSS VSS gf180mcu_fd_sc_mcu7t5v0__fill_1
X_066_ wire22/I _082_/A2 _083_/RN VDD VDD VSS VSS gf180mcu_fd_sc_mcu7t5v0__nor2_1
XFILLER_9_95 VDD VDD VSS VSS gf180mcu_fd_sc_mcu7t5v0__fillcap_4
X_049_ _083_/Q _065_/A1 VDD VDD VSS VSS gf180mcu_fd_sc_mcu7t5v0__clkinv_1
XFILLER_15_2 VDD VDD VSS VSS gf180mcu_fd_sc_mcu7t5v0__fillcap_64
XFILLER_29_70 VDD VDD VSS VSS gf180mcu_fd_sc_mcu7t5v0__fillcap_32
XFILLER_25_160 VDD VDD VSS VSS gf180mcu_fd_sc_mcu7t5v0__fill_1
XFILLER_16_193 VDD VDD VSS VSS gf180mcu_fd_sc_mcu7t5v0__fillcap_4
Xoutput3 output3/I clk_o VDD VDD VSS VSS gf180mcu_fd_sc_mcu7t5v0__dlyd_1
XTAP_TAPCELL_ROW_24_136 VDD VSS gf180mcu_fd_sc_mcu7t5v0__filltie
Xwire26 wire26/I wire26/Z VDD VDD VSS VSS gf180mcu_fd_sc_mcu7t5v0__buf_2
XTAP_TAPCELL_ROW_21_128 VDD VSS gf180mcu_fd_sc_mcu7t5v0__filltie
XFILLER_12_95 VDD VDD VSS VSS gf180mcu_fd_sc_mcu7t5v0__fillcap_8
X_082_ wire22/Z _082_/A2 _082_/ZN VDD VDD VSS VSS gf180mcu_fd_sc_mcu7t5v0__nor2_1
XFILLER_18_211 VDD VDD VSS VSS gf180mcu_fd_sc_mcu7t5v0__fillcap_16
XFILLER_15_236 VDD VDD VSS VSS gf180mcu_fd_sc_mcu7t5v0__fillcap_4
XFILLER_21_228 VDD VDD VSS VSS gf180mcu_fd_sc_mcu7t5v0__fillcap_8
XFILLER_23_72 VDD VDD VSS VSS gf180mcu_fd_sc_mcu7t5v0__fillcap_32
X_065_ _065_/A1 _106_/Q _065_/B _108_/D _083_/D VDD VDD VSS VSS gf180mcu_fd_sc_mcu7t5v0__oai211_1
XFILLER_12_239 VDD VDD VSS VSS gf180mcu_fd_sc_mcu7t5v0__fill_2
XFILLER_18_61 VDD VDD VSS VSS gf180mcu_fd_sc_mcu7t5v0__fillcap_4
X_048_ _084_/Q _063_/A1 VDD VDD VSS VSS gf180mcu_fd_sc_mcu7t5v0__clkinv_1
XFILLER_29_147 VDD VDD VSS VSS gf180mcu_fd_sc_mcu7t5v0__fillcap_16
XFILLER_29_169 VDD VDD VSS VSS gf180mcu_fd_sc_mcu7t5v0__fill_1
XFILLER_4_235 VDD VDD VSS VSS gf180mcu_fd_sc_mcu7t5v0__fillcap_4
Xoutput4 _089_/Q dac_ctrl[0] VDD VDD VSS VSS gf180mcu_fd_sc_mcu7t5v0__dlyd_1
XTAP_TAPCELL_ROW_27_145 VDD VSS gf180mcu_fd_sc_mcu7t5v0__filltie
XTAP_TAPCELL_ROW_24_137 VDD VSS gf180mcu_fd_sc_mcu7t5v0__filltie
XTAP_TAPCELL_ROW_21_129 VDD VSS gf180mcu_fd_sc_mcu7t5v0__filltie
XFILLER_3_76 VDD VDD VSS VSS gf180mcu_fd_sc_mcu7t5v0__fill_1
XFILLER_10_101 VDD VDD VSS VSS gf180mcu_fd_sc_mcu7t5v0__fillcap_4
XFILLER_27_212 VDD VDD VSS VSS gf180mcu_fd_sc_mcu7t5v0__fillcap_16
X_081_ wire22/I _082_/A2 _106_/RN VDD VDD VSS VSS gf180mcu_fd_sc_mcu7t5v0__nor2_1
XPHY_EDGE_ROW_25_Right_25 VDD VDD VSS VSS gf180mcu_fd_sc_mcu7t5v0__endcap
XPHY_EDGE_ROW_16_Right_16 VDD VDD VSS VSS gf180mcu_fd_sc_mcu7t5v0__endcap
XFILLER_5_2 VDD VDD VSS VSS gf180mcu_fd_sc_mcu7t5v0__fillcap_64
XFILLER_2_174 VDD VDD VSS VSS gf180mcu_fd_sc_mcu7t5v0__fill_1
X_064_ _064_/A1 _106_/Q _065_/B VDD VDD VSS VSS gf180mcu_fd_sc_mcu7t5v0__nand2_1
XPHY_EDGE_ROW_29_Left_59 VDD VDD VSS VSS gf180mcu_fd_sc_mcu7t5v0__endcap
XFILLER_21_207 VDD VDD VSS VSS gf180mcu_fd_sc_mcu7t5v0__fill_2
XFILLER_11_240 VDD VDD VSS VSS gf180mcu_fd_sc_mcu7t5v0__fill_1
X_047_ _085_/Q _061_/A1 VDD VDD VSS VSS gf180mcu_fd_sc_mcu7t5v0__clkinv_1
XFILLER_29_104 VDD VDD VSS VSS gf180mcu_fd_sc_mcu7t5v0__fillcap_32
XPHY_EDGE_ROW_2_Right_2 VDD VDD VSS VSS gf180mcu_fd_sc_mcu7t5v0__endcap
XFILLER_1_228 VDD VDD VSS VSS gf180mcu_fd_sc_mcu7t5v0__fillcap_8
XFILLER_20_2 VDD VDD VSS VSS gf180mcu_fd_sc_mcu7t5v0__fillcap_32
XFILLER_26_107 VDD VDD VSS VSS gf180mcu_fd_sc_mcu7t5v0__fillcap_16
XPHY_EDGE_ROW_16_Left_46 VDD VDD VSS VSS gf180mcu_fd_sc_mcu7t5v0__endcap
XFILLER_15_85 VDD VDD VSS VSS gf180mcu_fd_sc_mcu7t5v0__fillcap_4
XFILLER_15_96 VDD VDD VSS VSS gf180mcu_fd_sc_mcu7t5v0__fill_2
Xoutput5 _088_/Q dac_ctrl[1] VDD VDD VSS VSS gf180mcu_fd_sc_mcu7t5v0__dlyd_1
XTAP_TAPCELL_ROW_27_146 VDD VSS gf180mcu_fd_sc_mcu7t5v0__filltie
XTAP_TAPCELL_ROW_24_138 VDD VSS gf180mcu_fd_sc_mcu7t5v0__filltie
X_080_ wire22/I _080_/A2 _105_/RN VDD VDD VSS VSS gf180mcu_fd_sc_mcu7t5v0__nor2_1
XFILLER_12_53 VDD VDD VSS VSS gf180mcu_fd_sc_mcu7t5v0__fillcap_4
XFILLER_18_235 VDD VDD VSS VSS gf180mcu_fd_sc_mcu7t5v0__fillcap_4
XFILLER_2_197 VDD VDD VSS VSS gf180mcu_fd_sc_mcu7t5v0__fill_2
X_063_ _063_/A1 _105_/Q _063_/B _084_/D VDD VDD VSS VSS gf180mcu_fd_sc_mcu7t5v0__oai21_1
XPHY_EDGE_ROW_4_Left_34 VDD VDD VSS VSS gf180mcu_fd_sc_mcu7t5v0__endcap
X_046_ _086_/Q _059_/A1 VDD VDD VSS VSS gf180mcu_fd_sc_mcu7t5v0__clkinv_1
XFILLER_29_138 VDD VDD VSS VSS gf180mcu_fd_sc_mcu7t5v0__fill_2
XFILLER_13_2 VDD VDD VSS VSS gf180mcu_fd_sc_mcu7t5v0__fillcap_64
XFILLER_19_193 VDD VDD VSS VSS gf180mcu_fd_sc_mcu7t5v0__fillcap_16
XFILLER_25_174 VDD VDD VSS VSS gf180mcu_fd_sc_mcu7t5v0__fillcap_4
XFILLER_25_185 VDD VDD VSS VSS gf180mcu_fd_sc_mcu7t5v0__fillcap_16
Xoutput6 _087_/Q dac_ctrl[2] VDD VDD VSS VSS gf180mcu_fd_sc_mcu7t5v0__dlyd_1
XTAP_TAPCELL_ROW_27_147 VDD VSS gf180mcu_fd_sc_mcu7t5v0__filltie
XFILLER_0_240 VDD VDD VSS VSS gf180mcu_fd_sc_mcu7t5v0__fill_1
.ends
"}
C {lab_wire.sym} 210 -790 0 0 {name=p10 sig_type=std_logic lab=CLK_N}
C {lab_wire.sym} 1160 -830 0 0 {name=p12 sig_type=std_logic lab=VRef}
C {lab_wire.sym} 700 -1120 0 0 {name=p7 sig_type=std_logic lab=CLK}
C {lab_wire.sym} 350 -940 0 0 {name=p14 sig_type=std_logic lab=VDD}
C {lab_wire.sym} 700 -1100 0 0 {name=p4 sig_type=std_logic lab=VIN}
C {lab_wire.sym} 210 -670 0 0 {name=p6 sig_type=std_logic lab=RST}
C {lab_pin.sym} -665 -1000 1 0 {name=p28 sig_type=std_logic lab=CLK}
C {vsource.sym} -665 -930 0 0 {name=V8 
value= "PULSE(0 3.3 0 50p 50p 120n 250n)"
savecurrent=false}
C {gnd.sym} -665 -860 0 0 {name=l9 lab=0}
C {vsource.sym} -660 -700 0 0 {name=V3 
value=3.3
savecurrent=false}
C {gnd.sym} -660 -630 0 0 {name=l3 lab=0}
C {lab_pin.sym} -660 -770 1 0 {name=p30 sig_type=std_logic lab=VDD}
C {vsource.sym} -550 -700 0 0 {name=V1 
value="PULSE(3.3 0 0 1n 1n 15n 100000n)"
savecurrent=false}
C {gnd.sym} -550 -630 0 0 {name=l2 lab=0}
C {lab_pin.sym} -550 -770 1 0 {name=p16 sig_type=std_logic lab=RST}
C {lab_wire.sym} 760 -960 0 0 {name=p17 sig_type=std_logic lab=VDD}
C {vsource.sym} -850 -930 0 0 {name=V6 
value="sin(0.825 0.75 100k 0)"
savecurrent=false}
C {lab_pin.sym} -850 -1000 1 0 {name=p19 sig_type=std_logic lab=VIN}
C {gnd.sym} -850 -860 0 0 {name=l6 lab=0}
C {lab_wire.sym} 490 -710 2 0 {name=p20 sig_type=std_logic lab=DOUT0}
C {lab_wire.sym} 490 -690 2 0 {name=p21 sig_type=std_logic lab=DOUT1}
C {lab_wire.sym} 490 -670 2 0 {name=p22 sig_type=std_logic lab=DOUT2}
C {lab_wire.sym} 490 -650 2 0 {name=p23 sig_type=std_logic lab=DOUT3}
C {lab_wire.sym} 490 -630 2 0 {name=p24 sig_type=std_logic lab=DOUT4}
C {lab_wire.sym} 490 -610 2 0 {name=p25 sig_type=std_logic lab=DOUT5}
C {lab_wire.sym} 490 -590 2 0 {name=p26 sig_type=std_logic lab=DOUT6}
C {lab_wire.sym} 490 -570 2 0 {name=p27 sig_type=std_logic lab=DOUT7}
C {code_shown.sym} -1320 -1410 0 0 {name=MODELS only_toplevel=true
format="tcleval( @value )"
value="
.include $::180MCU_MODELS/design.ngspice
.include $PDK_ROOT/gf180mcuD/libs.ref/gf180mcu_fd_sc_mcu7t5v0/spice/gf180mcu_fd_sc_mcu7t5v0.spice
.lib $::180MCU_MODELS/sm141064.ngspice typical
.lib $::180MCU_MODELS/smbb000149.ngspice typical
.lib /foss/pdks/gf180mcuD/libs.tech/ngspice/sm141064.ngspice cap_mim
.lib "/foss/pdks/gf180mcuD/libs.tech/ngspice/sm141064.ngspice" mimcap_typical
"}
C {code_shown.sym} -1360 -1210 0 0 {name=s3 only_toplevel=true 
value="
.tran 1n 20000n uic
.ic v(VX)=1.65 v(VX_LSB)=1.65

.control
run
plot v(vin) v(vsample) v(vx) v(vx_lsb)
plot v(net1) v(outp) v(outn)
plot v(net2) v(net3) v(net4) v(net5) v(net6) v(net7) v(net8) v(net16)
plot v(dout0) v(dout1) v(dout2) v(dout3) v(dout4) v(dout5) v(dout6) v(dout7)
plot v(clk)
plot v(x2._108_/q)
.endc
"}
C {vsource.sym} -750 -700 0 0 {name=V2 
value=1.65
savecurrent=false}
C {gnd.sym} -750 -630 0 0 {name=l4 lab=0}
C {lab_pin.sym} -750 -770 1 0 {name=p29 sig_type=std_logic lab=VRef}
C {gnd.sym} -20 -620 0 0 {name=l5 lab=0}
C {gnd.sym} 350 -490 0 0 {name=l7 lab=0}
C {gnd.sym} 770 -670 0 0 {name=l8 lab=0}
C {gnd.sym} 1160 -890 1 0 {name=l10 lab=0}
C {gnd.sym} 880 -1020 0 0 {name=l11 lab=0}
C {lab_wire.sym} 110 -720 2 0 {name=p3 sig_type=std_logic lab=OUTP}
C {lab_wire.sym} 1500 -1100 0 0 {name=p11 sig_type=std_logic lab=VX}
C {lab_wire.sym} 1540 -1010 2 0 {name=p13 sig_type=std_logic lab=VX_LSB}
C {lab_wire.sym} 1030 -1030 0 0 {name=p15 sig_type=std_logic lab=VSAMPLE}
C {/foss/designs/proj_branch/chipathon-2026-ti-adc/analog/blocks/cdac/caps.sym} 1350 -830 0 0 {name=x6}
C {inverter_block.sym} 750 -810 0 0 {name=x1}
C {/foss/designs/proj_branch/chipathon-2026-ti-adc/analog/blocks/Double_Tail_Comparator/realcomp.sym} -20 -700 0 0 {name=x5}
C {/foss/designs/proj_branch/chipathon-2026-ti-adc/analog/blocks/transmission_gate/transmission_gate.sym} 880 -1100 0 0 {name=x3}
C {/foss/designs/proj_branch/chipathon-2026-ti-adc/analog/digital/SAR_ADC_LOGIC/sar_logic.sym} 340 -730 0 0 {name=X2 model=sar_adc_logic}
C {lab_pin.sym} -1005 -780 1 0 {name=p5 sig_type=std_logic lab=CLK_N}
C {vsource.sym} -1005 -710 0 0 {name=V9 
value= "PULSE(3.3 0 0 50p 50p 120n 250n)"
savecurrent=false}
C {gnd.sym} -1005 -640 0 0 {name=l1 lab=0}
C {vsource.sym} -180 -690 1 0 {name=V10
value="net17 0 0.825"
savecurrent=false}
C {gnd.sym} -230 -690 1 0 {name=l12 lab=0}
